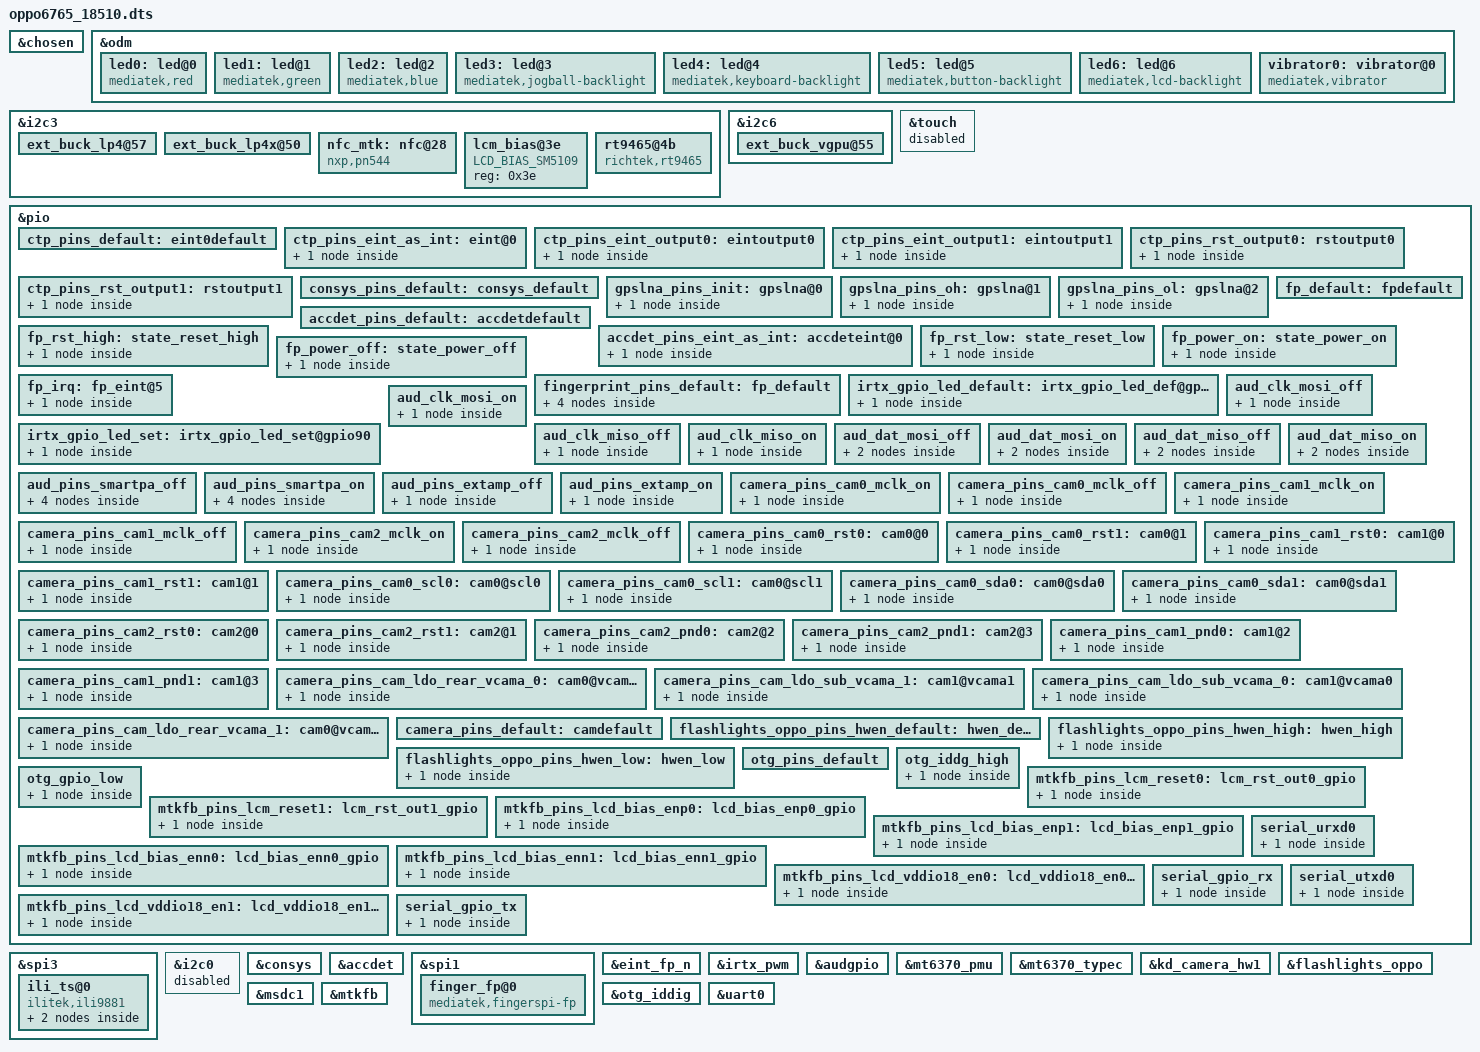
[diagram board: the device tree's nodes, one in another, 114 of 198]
#include <dt-bindings/interrupt-controller/arm-gic.h>
#include <dt-bindings/interrupt-controller/irq.h>
#include <dt-bindings/pinctrl/mt6765-pinfunc.h>
#include <dt-bindings/clock/mt6765-clk.h>
//#ifdef ODM_WT_EDIT
//Yanchao.Hu@ODM_WT.BSP.Storage.Sdcard, 2018/09/28, Modify for sdcard irq trigger states
#include <dt-bindings/mmc/mt6765-msdc.h>
//#endif

/dts-v1/;
/plugin/;

/* chosen */
&chosen {
	bootargs = "console=tty0 console=ttyS0,921600n1\
root=/dev/ram initrd=0x45000000,0x1000000 loglevel=8 \
androidboot.selinux=permissive androidboot.hardware=mt6765 \
initcall_debug=1 maxcpus=1";

	/* fpga may has no lk, we need to specify display info here */
	/* fb buffer is reserved using this dts by memory node above */
	atag,videolfb-fb_base_h = <0x0>;
	atag,videolfb-fb_base_l = <0x5e605000>;
	atag,videolfb-islcmfound = <1>;
	/* because no lk, so lcm is not inited */
	atag,videolfb-islcm_inited = <0>;
	atag,videolfb-fps= <6000>;
	atag,videolfb-vramSize= <0x017bb000>;
	atag,videolfb-lcmname= "nt35695B_fhd_dsi_cmd_auo_rt5081_drv";
};

&odm {
	led0:led@0 {
		compatible = "mediatek,red";
		led_mode = <0>;
		data = <1>;
		pwm_config = <0 0 0 0 0>;
	};
	led1:led@1 {
		compatible = "mediatek,green";
		led_mode = <0>;
		data = <1>;
		pwm_config = <0 0 0 0 0>;
	};
	led2:led@2 {
		compatible = "mediatek,blue";
		led_mode = <0>;
		data = <1>;
		pwm_config = <0 0 0 0 0>;
	};
	led3:led@3 {
		compatible = "mediatek,jogball-backlight";
		led_mode = <0>;
		data = <1>;
		pwm_config = <0 0 0 0 0>;
	};
	led4:led@4 {
		compatible = "mediatek,keyboard-backlight";
		led_mode = <0>;
		data = <1>;
		pwm_config = <0 0 0 0 0>;
	};
	led5:led@5 {
		compatible = "mediatek,button-backlight";
		led_mode = <0>;
		data = <1>;
		pwm_config = <0 0 0 0 0>;
	};
	led6:led@6 {
		compatible = "mediatek,lcd-backlight";
		led_mode = <4>;//ODM_WT_EDIT,backlight control by TDDIC
		data = <1>;
		pwm_config = <0 3 0 0 0>;
	};
	vibrator0:vibrator@0 {
		compatible = "mediatek,vibrator";
		vib_timer = <25>;
		vib_limit = <9>;
		vib_vol= <9>;
	};
};

&i2c3 {
	ext_buck_lp4@57 {
		regulator-name ="ext_buck_vdd2";
		regulator-min-microvolt = <300000>;
		regulator-max-microvolt = <1300000>;
		vsel_pin = <0>;
	};

	ext_buck_lp4x@50 {
		regulator-name ="ext_buck_vddq";
		regulator-min-microvolt = <300000>;
		regulator-max-microvolt = <1300000>;
		vsel_pin = <1>;
	};
/* #ifdef ODM_WT_EDIT */
	nfc_mtk:nfc@28 {
		compatible = "nxp,pn544";
		reg = <0x28>;
		pn544-irq = <&pio 97 0x0>;
		pn544-ven = <&pio 98 0x0>;
		pn544-fw-dwnld = <&pio 87 0x0>;
		pn544-clkreq = <&pio 89 0x0>;
		status = "okay";
	};
/* #endif */
};
/* #ifdef ODM_WT_EDIT */
/* Benzhong.Hou@ODM_WT.MM.Display.Lcd, 2018/10/10, add lcd gate ic device description */
/* lcd gate ic device description */
&i2c3 {
      lcm_bias@3e{
               compatible = "LCD_BIAS_SM5109","LCD_BIAS_NT50358A";
               reg = <0x3e>;
               status = "okay";
       };
};
/* Benzhong.Hou@ODM_WT.MM.Display.Lcd, 2018/10/10, add lcd gate ic device description */
/* #endif */
&i2c6 {
	ext_buck_vgpu@55 {
		regulator-name ="ext_buck_vgpu";
		regulator-min-microvolt = <300000>;
		regulator-max-microvolt = <1300000>;
		vsel_pin = <2>;
	};
};
/* TOUCH start */
&touch {
	tpd-resolution = <1080 1920>;
	use-tpd-button = <0>;
	tpd-key-num = <3>;
	tpd-key-local= <139 172 158 0>;
	tpd-key-dim-local = <90 883 100 40 230
				 883 100 40 370 883 100 40 0 0 0 0>;
	tpd-max-touch-num = <5>;
	tpd-filter-enable = <1>;
	tpd-filter-pixel-density = <146>;
	tpd-filter-custom-prameters = <0 0 0 0 0 0 0 0 0 0 0 0>;
	tpd-filter-custom-speed = <0 0 0>;
	pinctrl-names = "default", "state_eint_as_int", "state_eint_output0",
		"state_eint_output1", "state_rst_output0", "state_rst_output1";
	pinctrl-0 = <&ctp_pins_default>;
	pinctrl-1 = <&ctp_pins_eint_as_int>;
	pinctrl-2 = <&ctp_pins_eint_output0>;
	pinctrl-3 = <&ctp_pins_eint_output1>;
	pinctrl-4 = <&ctp_pins_rst_output0>;
	pinctrl-5 = <&ctp_pins_rst_output1>;
//#ifdef ODM_WT_EDIT
//Bin.Su@ODM_WT.BSP.TouchScreen, 2018/08/09, Disable no use dts for TouchScreen BringUp
	status = "disable";
//#endif
};
&pio {
	ctp_pins_default: eint0default {
	};
	ctp_pins_eint_as_int: eint@0 {
		pins_cmd_dat {
			pinmux = <PINMUX_GPIO0__FUNC_GPIO0>;
			slew-rate = <0>;
			bias-disable;
		};
	};
	ctp_pins_eint_output0: eintoutput0 {
		pins_cmd_dat {
			pinmux = <PINMUX_GPIO0__FUNC_GPIO0>;
			slew-rate = <1>;
			input-low;
		};
	};
	ctp_pins_eint_output1: eintoutput1 {
		pins_cmd_dat {
			pinmux = <PINMUX_GPIO0__FUNC_GPIO0>;
			slew-rate = <1>;
			input-high;
		};
	};
	ctp_pins_rst_output0: rstoutput0 {
		pins_cmd_dat {
			pinmux = <PINMUX_GPIO174__FUNC_GPIO174>;
			slew-rate = <1>;
			output-low;
		};
	};
	ctp_pins_rst_output1: rstoutput1 {
		pins_cmd_dat {
			pinmux = <PINMUX_GPIO174__FUNC_GPIO174>;
			slew-rate = <1>;
			output-high;
		};
	};
};
/* TOUCH end */

//#ifdef ODM_WT_EDIT
//Bin.Su@ODM_WT.BSP.TouchScreen, 2018/08/09, Add dts for TouchScreen BringUp
/*SPI touch start*/
&spi3 {
	#address-cells = <1>;
	#size-cells = <0>;
	ili_ts@0 {
		reg = <0>;
		compatible = "ilitek,ili9881","mediatek,cap_touch","novatek,NVT-ts-spi","himax,hx83112";
		touch,irq-gpio = <&pio 0 0>;
		touch,reset-gpio = <&pio 174 0>;

		focaltech,max-touch-number = <10>;
		focaltech,display-coords = <0 0 720 1520>;

		novatek,irq-gpio = <&pio 0 0>;
		novatek,reset-gpio = <&pio 174 0>;
		novatek,reset_global_gpio = <&pio 45 0>;
		/* 672A, 525B */
		novatek,swrst-n8-addr = <0x03F0FE>;
		/* MP */
		//novatek,mp-support-dt;

		spi-max-frequency = <9600000>;
		/*netlink-event = <30>;*/
		/* touchpanel configuration */
		touchpanel,rst-gpio = <&pio 174 0x0>;
		touchpanel,irq-gpio = <&pio 0 0x0>;
		touchpanel,open_short_not_use_fw;

		/*GPIO for LCD ID PIN*/
		touchpanel,id0-gpio = <&pio 169 0x0>;
		touchpanel,id1-gpio = <&pio 168 0x0>;
		touchpanel,id2-gpio = <&pio 172 0x0>;

		pinctrl-names = "default", "state_eint_as_int", "state_eint_output0",
		"state_eint_output1", "state_rst_output0", "state_rst_output1";
		pinctrl-0 = <&ctp_pins_default>;
		pinctrl-1 = <&ctp_pins_eint_as_int>;
		pinctrl-2 = <&ctp_pins_eint_output0>;
		pinctrl-3 = <&ctp_pins_eint_output1>;
		pinctrl-4 = <&ctp_pins_rst_output0>;
		pinctrl-5 = <&ctp_pins_rst_output1>;
		status = "ok";
		novatek,mp-support-dt;
		novatek-mp-criteria-tcl@0 {
			#address-cells = <1>;
			#size-cells = <0>;
			compatible = "novatek-mp-criteria-tcl";

			/* MP Config */
			IC_X_CFG_SIZE = <18>;
			IC_Y_CFG_SIZE = <32>;
			IC_KEY_CFG_SIZE = <4>;
			X_Channel = <18>;
			Y_Channel = <32>;
			AIN_X = <0 1 2 3 4 5 6 7 8 9 10 11 12 13 14 15 16 17>;
			AIN_Y = <0 1 2 3 4 5 6 7 8 9 10 11 12 13 14 15 16 17 18 19
								20 21 22 23 24 25 26 27 28 29 30 31>;
			AIN_KEY = <0 1 2 0xFF>;

			/* MP Criteria */
			PS_Config_Lmt_Short_Rawdata_P = <
				14008 14008 14008 14008 14008 14008 14008 14008 14008 14008 14008 14008 14008 14008 14008 14008 14008 14008
				14008 14008 14008 14008 14008 14008 14008 14008 14008 14008 14008 14008 14008 14008 14008 14008 14008 14008
				14008 14008 14008 14008 14008 14008 14008 14008 14008 14008 14008 14008 14008 14008 14008 14008 14008 14008
				14008 14008 14008 14008 14008 14008 14008 14008 14008 14008 14008 14008 14008 14008 14008 14008 14008 14008
				14008 14008 14008 14008 14008 14008 14008 14008 14008 14008 14008 14008 14008 14008 14008 14008 14008 14008
				14008 14008 14008 14008 14008 14008 14008 14008 14008 14008 14008 14008 14008 14008 14008 14008 14008 14008
				14008 14008 14008 14008 14008 14008 14008 14008 14008 14008 14008 14008 14008 14008 14008 14008 14008 14008
				14008 14008 14008 14008 14008 14008 14008 14008 14008 14008 14008 14008 14008 14008 14008 14008 14008 14008
				14008 14008 14008 14008 14008 14008 14008 14008 14008 14008 14008 14008 14008 14008 14008 14008 14008 14008
				14008 14008 14008 14008 14008 14008 14008 14008 14008 14008 14008 14008 14008 14008 14008 14008 14008 14008
				14008 14008 14008 14008 14008 14008 14008 14008 14008 14008 14008 14008 14008 14008 14008 14008 14008 14008
				14008 14008 14008 14008 14008 14008 14008 14008 14008 14008 14008 14008 14008 14008 14008 14008 14008 14008
				14008 14008 14008 14008 14008 14008 14008 14008 14008 14008 14008 14008 14008 14008 14008 14008 14008 14008
				14008 14008 14008 14008 14008 14008 14008 14008 14008 14008 14008 14008 14008 14008 14008 14008 14008 14008
				14008 14008 14008 14008 14008 14008 14008 14008 14008 14008 14008 14008 14008 14008 14008 14008 14008 14008
				14008 14008 14008 14008 14008 14008 14008 14008 14008 14008 14008 14008 14008 14008 14008 14008 14008 14008
				14008 14008 14008 14008 14008 14008 14008 14008 14008 14008 14008 14008 14008 14008 14008 14008 14008 14008
				14008 14008 14008 14008 14008 14008 14008 14008 14008 14008 14008 14008 14008 14008 14008 14008 14008 14008
				14008 14008 14008 14008 14008 14008 14008 14008 14008 14008 14008 14008 14008 14008 14008 14008 14008 14008
				14008 14008 14008 14008 14008 14008 14008 14008 14008 14008 14008 14008 14008 14008 14008 14008 14008 14008
				14008 14008 14008 14008 14008 14008 14008 14008 14008 14008 14008 14008 14008 14008 14008 14008 14008 14008
				14008 14008 14008 14008 14008 14008 14008 14008 14008 14008 14008 14008 14008 14008 14008 14008 14008 14008
				14008 14008 14008 14008 14008 14008 14008 14008 14008 14008 14008 14008 14008 14008 14008 14008 14008 14008
				14008 14008 14008 14008 14008 14008 14008 14008 14008 14008 14008 14008 14008 14008 14008 14008 14008 14008
				14008 14008 14008 14008 14008 14008 14008 14008 14008 14008 14008 14008 14008 14008 14008 14008 14008 14008
				14008 14008 14008 14008 14008 14008 14008 14008 14008 14008 14008 14008 14008 14008 14008 14008 14008 14008
				14008 14008 14008 14008 14008 14008 14008 14008 14008 14008 14008 14008 14008 14008 14008 14008 14008 14008
				14008 14008 14008 14008 14008 14008 14008 14008 14008 14008 14008 14008 14008 14008 14008 14008 14008 14008
				14008 14008 14008 14008 14008 14008 14008 14008 14008 14008 14008 14008 14008 14008 14008 14008 14008 14008
				14008 14008 14008 14008 14008 14008 14008 14008 14008 14008 14008 14008 14008 14008 14008 14008 14008 14008
				14008 14008 14008 14008 14008 14008 14008 14008 14008 14008 14008 14008 14008 14008 14008 14008 14008 14008
				14008 14008 14008 14008 14008 14008 14008 14008 14008 14008 14008 14008 14008 14008 14008 14008 14008 14008
				>;

			PS_Config_Lmt_Short_Rawdata_N = <
				11376 11376 11376 11376 11376 11376 11376 11376 11376 11376 11376 11376 11376 11376 11376 11376 11376 11376
				11376 11376 11376 11376 11376 11376 11376 11376 11376 11376 11376 11376 11376 11376 11376 11376 11376 11376
				11376 11376 11376 11376 11376 11376 11376 11376 11376 11376 11376 11376 11376 11376 11376 11376 11376 11376
				11376 11376 11376 11376 11376 11376 11376 11376 11376 11376 11376 11376 11376 11376 11376 11376 11376 11376
				11376 11376 11376 11376 11376 11376 11376 11376 11376 11376 11376 11376 11376 11376 11376 11376 11376 11376
				11376 11376 11376 11376 11376 11376 11376 11376 11376 11376 11376 11376 11376 11376 11376 11376 11376 11376
				11376 11376 11376 11376 11376 11376 11376 11376 11376 11376 11376 11376 11376 11376 11376 11376 11376 11376
				11376 11376 11376 11376 11376 11376 11376 11376 11376 11376 11376 11376 11376 11376 11376 11376 11376 11376
				11376 11376 11376 11376 11376 11376 11376 11376 11376 11376 11376 11376 11376 11376 11376 11376 11376 11376
				11376 11376 11376 11376 11376 11376 11376 11376 11376 11376 11376 11376 11376 11376 11376 11376 11376 11376
				11376 11376 11376 11376 11376 11376 11376 11376 11376 11376 11376 11376 11376 11376 11376 11376 11376 11376
				11376 11376 11376 11376 11376 11376 11376 11376 11376 11376 11376 11376 11376 11376 11376 11376 11376 11376
				11376 11376 11376 11376 11376 11376 11376 11376 11376 11376 11376 11376 11376 11376 11376 11376 11376 11376
				11376 11376 11376 11376 11376 11376 11376 11376 11376 11376 11376 11376 11376 11376 11376 11376 11376 11376
				11376 11376 11376 11376 11376 11376 11376 11376 11376 11376 11376 11376 11376 11376 11376 11376 11376 11376
				11376 11376 11376 11376 11376 11376 11376 11376 11376 11376 11376 11376 11376 11376 11376 11376 11376 11376
				11376 11376 11376 11376 11376 11376 11376 11376 11376 11376 11376 11376 11376 11376 11376 11376 11376 11376
				11376 11376 11376 11376 11376 11376 11376 11376 11376 11376 11376 11376 11376 11376 11376 11376 11376 11376
				11376 11376 11376 11376 11376 11376 11376 11376 11376 11376 11376 11376 11376 11376 11376 11376 11376 11376
				11376 11376 11376 11376 11376 11376 11376 11376 11376 11376 11376 11376 11376 11376 11376 11376 11376 11376
				11376 11376 11376 11376 11376 11376 11376 11376 11376 11376 11376 11376 11376 11376 11376 11376 11376 11376
				11376 11376 11376 11376 11376 11376 11376 11376 11376 11376 11376 11376 11376 11376 11376 11376 11376 11376
				11376 11376 11376 11376 11376 11376 11376 11376 11376 11376 11376 11376 11376 11376 11376 11376 11376 11376
				11376 11376 11376 11376 11376 11376 11376 11376 11376 11376 11376 11376 11376 11376 11376 11376 11376 11376
				11376 11376 11376 11376 11376 11376 11376 11376 11376 11376 11376 11376 11376 11376 11376 11376 11376 11376
				11376 11376 11376 11376 11376 11376 11376 11376 11376 11376 11376 11376 11376 11376 11376 11376 11376 11376
				11376 11376 11376 11376 11376 11376 11376 11376 11376 11376 11376 11376 11376 11376 11376 11376 11376 11376
				11376 11376 11376 11376 11376 11376 11376 11376 11376 11376 11376 11376 11376 11376 11376 11376 11376 11376
				11376 11376 11376 11376 11376 11376 11376 11376 11376 11376 11376 11376 11376 11376 11376 11376 11376 11376
				11376 11376 11376 11376 11376 11376 11376 11376 11376 11376 11376 11376 11376 11376 11376 11376 11376 11376
				11376 11376 11376 11376 11376 11376 11376 11376 11376 11376 11376 11376 11376 11376 11376 11376 11376 11376
				11376 11376 11376 11376 11376 11376 11376 11376 11376 11376 11376 11376 11376 11376 11376 11376 11376 11376
				>;

			PS_Config_Lmt_Open_Rawdata_P = <
				65535 4000 4000 4000 4000 4000 4000 4000 65535 65535 4000 4000 4000 4000 4000 4000 4000 65535
				4000 4000 4000 4000 4000 4000 4000 4000 4000 4000 4000 4000 4000 4000 4000 4000 4000 4000
				4000 4000 4000 4000 4000 4000 4000 4000 4000 4000 4000 4000 4000 4000 4000 4000 4000 4000
				4000 4000 4000 4000 4000 4000 4000 4000 4000 4000 4000 4000 4000 4000 4000 4000 4000 4000
				4000 4000 4000 4000 4000 4000 4000 4000 4000 4000 4000 4000 4000 4000 4000 4000 4000 4000
				4000 4000 4000 4000 4000 4000 4000 4000 4000 4000 4000 4000 4000 4000 4000 4000 4000 4000
				4000 4000 4000 4000 4000 4000 4000 4000 4000 4000 4000 4000 4000 4000 4000 4000 4000 4000
				4000 4000 4000 4000 4000 4000 4000 4000 4000 4000 4000 4000 4000 4000 4000 4000 4000 4000
				4000 4000 4000 4000 4000 4000 4000 4000 4000 4000 4000 4000 4000 4000 4000 4000 4000 4000
				4000 4000 4000 4000 4000 4000 4000 4000 4000 4000 4000 4000 4000 4000 4000 4000 4000 4000
				4000 4000 4000 4000 4000 4000 4000 4000 4000 4000 4000 4000 4000 4000 4000 4000 4000 4000
				4000 4000 4000 4000 4000 4000 4000 4000 4000 4000 4000 4000 4000 4000 4000 4000 4000 4000
				4000 4000 4000 4000 4000 4000 4000 4000 4000 4000 4000 4000 4000 4000 4000 4000 4000 4000
				4000 4000 4000 4000 4000 4000 4000 4000 4000 4000 4000 4000 4000 4000 4000 4000 4000 4000
				4000 4000 4000 4000 4000 4000 4000 4000 4000 4000 4000 4000 4000 4000 4000 4000 4000 4000
				4000 4000 4000 4000 4000 4000 4000 4000 4000 4000 4000 4000 4000 4000 4000 4000 4000 4000
				4000 4000 4000 4000 4000 4000 4000 4000 4000 4000 4000 4000 4000 4000 4000 4000 4000 4000
				4000 4000 4000 4000 4000 4000 4000 4000 4000 4000 4000 4000 4000 4000 4000 4000 4000 4000
				4000 4000 4000 4000 4000 4000 4000 4000 4000 4000 4000 4000 4000 4000 4000 4000 4000 4000
				4000 4000 4000 4000 4000 4000 4000 4000 4000 4000 4000 4000 4000 4000 4000 4000 4000 4000
				4000 4000 4000 4000 4000 4000 4000 4000 4000 4000 4000 4000 4000 4000 4000 4000 4000 4000
				4000 4000 4000 4000 4000 4000 4000 4000 4000 4000 4000 4000 4000 4000 4000 4000 4000 4000
				4000 4000 4000 4000 4000 4000 4000 4000 4000 4000 4000 4000 4000 4000 4000 4000 4000 4000
				4000 4000 4000 4000 4000 4000 4000 4000 4000 4000 4000 4000 4000 4000 4000 4000 4000 4000
				4000 4000 4000 4000 4000 4000 4000 4000 4000 4000 4000 4000 4000 4000 4000 4000 4000 4000
				4000 4000 4000 4000 4000 4000 4000 4000 4000 4000 4000 4000 4000 4000 4000 4000 4000 4000
				4000 4000 4000 4000 4000 4000 4000 4000 4000 4000 4000 4000 4000 4000 4000 4000 4000 4000
				4000 4000 4000 4000 4000 4000 4000 4000 4000 4000 4000 4000 4000 4000 4000 4000 4000 4000
				4000 4000 4000 4000 4000 4000 4000 4000 4000 4000 4000 4000 4000 4000 4000 4000 4000 4000
				4000 4000 4000 4000 4000 4000 4000 4000 4000 4000 4000 4000 4000 4000 4000 4000 4000 4000
				4000 4000 4000 4000 4000 4000 4000 4000 4000 4000 4000 4000 4000 4000 4000 4000 4000 4000
				4000 4000 4000 4000 4000 4000 4000 4000 4000 4000 4000 4000 4000 4000 4000 4000 4000 4000
				>;

			PS_Config_Lmt_Open_Rawdata_N = <
				0 400 400 400 400 400 400 400 0 0 400 400 400 400 400 400 400 0
				400 400 400 400 400 400 400 400 400 400 400 400 400 400 400 400 400 400
				400 400 400 400 400 400 400 400 400 400 400 400 400 400 400 400 400 400
				400 400 400 400 400 400 400 400 400 400 400 400 400 400 400 400 400 400
				400 400 400 400 400 400 400 400 400 400 400 400 400 400 400 400 400 400
				400 400 400 400 400 400 400 400 400 400 400 400 400 400 400 400 400 400
				400 400 400 400 400 400 400 400 400 400 400 400 400 400 400 400 400 400
				400 400 400 400 400 400 400 400 400 400 400 400 400 400 400 400 400 400
				400 400 400 400 400 400 400 400 400 400 400 400 400 400 400 400 400 400
				400 400 400 400 400 400 400 400 400 400 400 400 400 400 400 400 400 400
				400 400 400 400 400 400 400 400 400 400 400 400 400 400 400 400 400 400
				400 400 400 400 400 400 400 400 400 400 400 400 400 400 400 400 400 400
				400 400 400 400 400 400 400 400 400 400 400 400 400 400 400 400 400 400
				400 400 400 400 400 400 400 400 400 400 400 400 400 400 400 400 400 400
				400 400 400 400 400 400 400 400 400 400 400 400 400 400 400 400 400 400
				400 400 400 400 400 400 400 400 400 400 400 400 400 400 400 400 400 400
				400 400 400 400 400 400 400 400 400 400 400 400 400 400 400 400 400 400
				400 400 400 400 400 400 400 400 400 400 400 400 400 400 400 400 400 400
				400 400 400 400 400 400 400 400 400 400 400 400 400 400 400 400 400 400
				400 400 400 400 400 400 400 400 400 400 400 400 400 400 400 400 400 400
				400 400 400 400 400 400 400 400 400 400 400 400 400 400 400 400 400 400
				400 400 400 400 400 400 400 400 400 400 400 400 400 400 400 400 400 400
				400 400 400 400 400 400 400 400 400 400 400 400 400 400 400 400 400 400
				400 400 400 400 400 400 400 400 400 400 400 400 400 400 400 400 400 400
				400 400 400 400 400 400 400 400 400 400 400 400 400 400 400 400 400 400
				400 400 400 400 400 400 400 400 400 400 400 400 400 400 400 400 400 400
				400 400 400 400 400 400 400 400 400 400 400 400 400 400 400 400 400 400
				400 400 400 400 400 400 400 400 400 400 400 400 400 400 400 400 400 400
				400 400 400 400 400 400 400 400 400 400 400 400 400 400 400 400 400 400
				400 400 400 400 400 400 400 400 400 400 400 400 400 400 400 400 400 400
				400 400 400 400 400 400 400 400 400 400 400 400 400 400 400 400 400 400
				400 400 400 400 400 400 400 400 400 400 400 400 400 400 400 400 400 400
				>;

			PS_Config_Lmt_FW_Rawdata_P = <
				65535 1600 1600 1600 1600 1600 1600 1600 65535 65535 1600 1600 1600 1600 1600 1600 1600 65535
				1600 1600 1600 1600 1600 1600 1600 1600 1600 1600 1600 1600 1600 1600 1600 1600 1600 1600
				1600 1600 1600 1600 1600 1600 1600 1600 1600 1600 1600 1600 1600 1600 1600 1600 1600 1600
				1600 1600 1600 1600 1600 1600 1600 1600 1600 1600 1600 1600 1600 1600 1600 1600 1600 1600
				1600 1600 1600 1600 1600 1600 1600 1600 1600 1600 1600 1600 1600 1600 1600 1600 1600 1600
				1600 1600 1600 1600 1600 1600 1600 1600 1600 1600 1600 1600 1600 1600 1600 1600 1600 1600
				1600 1600 1600 1600 1600 1600 1600 1600 1600 1600 1600 1600 1600 1600 1600 1600 1600 1600
				1600 1600 1600 1600 1600 1600 1600 1600 1600 1600 1600 1600 1600 1600 1600 1600 1600 1600
				1600 1600 1600 1600 1600 1600 1600 1600 1600 1600 1600 1600 1600 1600 1600 1600 1600 1600
				1600 1600 1600 1600 1600 1600 1600 1600 1600 1600 1600 1600 1600 1600 1600 1600 1600 1600
				1600 1600 1600 1600 1600 1600 1600 1600 1600 1600 1600 1600 1600 1600 1600 1600 1600 1600
				1600 1600 1600 1600 1600 1600 1600 1600 1600 1600 1600 1600 1600 1600 1600 1600 1600 1600
				1600 1600 1600 1600 1600 1600 1600 1600 1600 1600 1600 1600 1600 1600 1600 1600 1600 1600
				1600 1600 1600 1600 1600 1600 1600 1600 1600 1600 1600 1600 1600 1600 1600 1600 1600 1600
				1600 1600 1600 1600 1600 1600 1600 1600 1600 1600 1600 1600 1600 1600 1600 1600 1600 1600
				1600 1600 1600 1600 1600 1600 1600 1600 1600 1600 1600 1600 1600 1600 1600 1600 1600 1600
				1600 1600 1600 1600 1600 1600 1600 1600 1600 1600 1600 1600 1600 1600 1600 1600 1600 1600
				1600 1600 1600 1600 1600 1600 1600 1600 1600 1600 1600 1600 1600 1600 1600 1600 1600 1600
				1600 1600 1600 1600 1600 1600 1600 1600 1600 1600 1600 1600 1600 1600 1600 1600 1600 1600
				1600 1600 1600 1600 1600 1600 1600 1600 1600 1600 1600 1600 1600 1600 1600 1600 1600 1600
				1600 1600 1600 1600 1600 1600 1600 1600 1600 1600 1600 1600 1600 1600 1600 1600 1600 1600
				1600 1600 1600 1600 1600 1600 1600 1600 1600 1600 1600 1600 1600 1600 1600 1600 1600 1600
				1600 1600 1600 1600 1600 1600 1600 1600 1600 1600 1600 1600 1600 1600 1600 1600 1600 1600
				1600 1600 1600 1600 1600 1600 1600 1600 1600 1600 1600 1600 1600 1600 1600 1600 1600 1600
				1600 1600 1600 1600 1600 1600 1600 1600 1600 1600 1600 1600 1600 1600 1600 1600 1600 1600
				1600 1600 1600 1600 1600 1600 1600 1600 1600 1600 1600 1600 1600 1600 1600 1600 1600 1600
				1600 1600 1600 1600 1600 1600 1600 1600 1600 1600 1600 1600 1600 1600 1600 1600 1600 1600
				1600 1600 1600 1600 1600 1600 1600 1600 1600 1600 1600 1600 1600 1600 1600 1600 1600 1600
				1600 1600 1600 1600 1600 1600 1600 1600 1600 1600 1600 1600 1600 1600 1600 1600 1600 1600
				1600 1600 1600 1600 1600 1600 1600 1600 1600 1600 1600 1600 1600 1600 1600 1600 1600 1600
				1600 1600 1600 1600 1600 1600 1600 1600 1600 1600 1600 1600 1600 1600 1600 1600 1600 1600
				1600 1600 1600 1600 1600 1600 1600 1600 1600 1600 1600 1600 1600 1600 1600 1600 1600 1600
				>;

			PS_Config_Lmt_FW_Rawdata_N = <
				0 200 200 200 200 200 200 200 0 0 200 200 200 200 200 200 200 0
				200 200 200 200 200 200 200 200 200 200 200 200 200 200 200 200 200 200
				200 200 200 200 200 200 200 200 200 200 200 200 200 200 200 200 200 200
				200 200 200 200 200 200 200 200 200 200 200 200 200 200 200 200 200 200
				200 200 200 200 200 200 200 200 200 200 200 200 200 200 200 200 200 200
				200 200 200 200 200 200 200 200 200 200 200 200 200 200 200 200 200 200
				200 200 200 200 200 200 200 200 200 200 200 200 200 200 200 200 200 200
				200 200 200 200 200 200 200 200 200 200 200 200 200 200 200 200 200 200
				200 200 200 200 200 200 200 200 200 200 200 200 200 200 200 200 200 200
				200 200 200 200 200 200 200 200 200 200 200 200 200 200 200 200 200 200
				200 200 200 200 200 200 200 200 200 200 200 200 200 200 200 200 200 200
				200 200 200 200 200 200 200 200 200 200 200 200 200 200 200 200 200 200
				200 200 200 200 200 200 200 200 200 200 200 200 200 200 200 200 200 200
				200 200 200 200 200 200 200 200 200 200 200 200 200 200 200 200 200 200
				200 200 200 200 200 200 200 200 200 200 200 200 200 200 200 200 200 200
				200 200 200 200 200 200 200 200 200 200 200 200 200 200 200 200 200 200
				200 200 200 200 200 200 200 200 200 200 200 200 200 200 200 200 200 200
				200 200 200 200 200 200 200 200 200 200 200 200 200 200 200 200 200 200
				200 200 200 200 200 200 200 200 200 200 200 200 200 200 200 200 200 200
				200 200 200 200 200 200 200 200 200 200 200 200 200 200 200 200 200 200
				200 200 200 200 200 200 200 200 200 200 200 200 200 200 200 200 200 200
				200 200 200 200 200 200 200 200 200 200 200 200 200 200 200 200 200 200
				200 200 200 200 200 200 200 200 200 200 200 200 200 200 200 200 200 200
				200 200 200 200 200 200 200 200 200 200 200 200 200 200 200 200 200 200
				200 200 200 200 200 200 200 200 200 200 200 200 200 200 200 200 200 200
				200 200 200 200 200 200 200 200 200 200 200 200 200 200 200 200 200 200
				200 200 200 200 200 200 200 200 200 200 200 200 200 200 200 200 200 200
				200 200 200 200 200 200 200 200 200 200 200 200 200 200 200 200 200 200
				200 200 200 200 200 200 200 200 200 200 200 200 200 200 200 200 200 200
				200 200 200 200 200 200 200 200 200 200 200 200 200 200 200 200 200 200
				200 200 200 200 200 200 200 200 200 200 200 200 200 200 200 200 200 200
				200 200 200 200 200 200 200 200 200 200 200 200 200 200 200 200 200 200
				>;

			PS_Config_Lmt_FW_CC_P = <
				200 200 200 200 200 200 200 200 200 200 200 200 200 200 200 200 200 200
				200 200 200 200 200 200 200 200 200 200 200 200 200 200 200 200 200 200
				200 200 200 200 200 200 200 200 200 200 200 200 200 200 200 200 200 200
				200 200 200 200 200 200 200 200 200 200 200 200 200 200 200 200 200 200
				200 200 200 200 200 200 200 200 200 200 200 200 200 200 200 200 200 200
				200 200 200 200 200 200 200 200 200 200 200 200 200 200 200 200 200 200
				200 200 200 200 200 200 200 200 200 200 200 200 200 200 200 200 200 200
				200 200 200 200 200 200 200 200 200 200 200 200 200 200 200 200 200 200
				200 200 200 200 200 200 200 200 200 200 200 200 200 200 200 200 200 200
				200 200 200 200 200 200 200 200 200 200 200 200 200 200 200 200 200 200
				200 200 200 200 200 200 200 200 200 200 200 200 200 200 200 200 200 200
				200 200 200 200 200 200 200 200 200 200 200 200 200 200 200 200 200 200
				200 200 200 200 200 200 200 200 200 200 200 200 200 200 200 200 200 200
				200 200 200 200 200 200 200 200 200 200 200 200 200 200 200 200 200 200
				200 200 200 200 200 200 200 200 200 200 200 200 200 200 200 200 200 200
				200 200 200 200 200 200 200 200 200 200 200 200 200 200 200 200 200 200
				200 200 200 200 200 200 200 200 200 200 200 200 200 200 200 200 200 200
				200 200 200 200 200 200 200 200 200 200 200 200 200 200 200 200 200 200
				200 200 200 200 200 200 200 200 200 200 200 200 200 200 200 200 200 200
				200 200 200 200 200 200 200 200 200 200 200 200 200 200 200 200 200 200
				200 200 200 200 200 200 200 200 200 200 200 200 200 200 200 200 200 200
				200 200 200 200 200 200 200 200 200 200 200 200 200 200 200 200 200 200
				200 200 200 200 200 200 200 200 200 200 200 200 200 200 200 200 200 200
				200 200 200 200 200 200 200 200 200 200 200 200 200 200 200 200 200 200
				200 200 200 200 200 200 200 200 200 200 200 200 200 200 200 200 200 200
				200 200 200 200 200 200 200 200 200 200 200 200 200 200 200 200 200 200
				200 200 200 200 200 200 200 200 200 200 200 200 200 200 200 200 200 200
				200 200 200 200 200 200 200 200 200 200 200 200 200 200 200 200 200 200
				200 200 200 200 200 200 200 200 200 200 200 200 200 200 200 200 200 200
				200 200 200 200 200 200 200 200 200 200 200 200 200 200 200 200 200 200
				200 200 200 200 200 200 200 200 200 200 200 200 200 200 200 200 200 200
				200 200 200 200 200 200 200 200 200 200 200 200 200 200 200 200 200 200
				>;

			PS_Config_Lmt_FW_CC_N = <
				0 30 30 30 30 30 30 30 0 0 30 30 30 30 30 30 30 0
				30 30 30 30 30 30 30 30 30 30 30 30 30 30 30 30 30 30
				30 30 30 30 30 30 30 30 30 30 30 30 30 30 30 30 30 30
				30 30 30 30 30 30 30 30 30 30 30 30 30 30 30 30 30 30
				30 30 30 30 30 30 30 30 30 30 30 30 30 30 30 30 30 30
				30 30 30 30 30 30 30 30 30 30 30 30 30 30 30 30 30 30
				30 30 30 30 30 30 30 30 30 30 30 30 30 30 30 30 30 30
				30 30 30 30 30 30 30 30 30 30 30 30 30 30 30 30 30 30
				30 30 30 30 30 30 30 30 30 30 30 30 30 30 30 30 30 30
				30 30 30 30 30 30 30 30 30 30 30 30 30 30 30 30 30 30
				30 30 30 30 30 30 30 30 30 30 30 30 30 30 30 30 30 30
				30 30 30 30 30 30 30 30 30 30 30 30 30 30 30 30 30 30
				30 30 30 30 30 30 30 30 30 30 30 30 30 30 30 30 30 30
				30 30 30 30 30 30 30 30 30 30 30 30 30 30 30 30 30 30
				30 30 30 30 30 30 30 30 30 30 30 30 30 30 30 30 30 30
				30 30 30 30 30 30 30 30 30 30 30 30 30 30 30 30 30 30
				30 30 30 30 30 30 30 30 30 30 30 30 30 30 30 30 30 30
				30 30 30 30 30 30 30 30 30 30 30 30 30 30 30 30 30 30
				30 30 30 30 30 30 30 30 30 30 30 30 30 30 30 30 30 30
				30 30 30 30 30 30 30 30 30 30 30 30 30 30 30 30 30 30
				30 30 30 30 30 30 30 30 30 30 30 30 30 30 30 30 30 30
				30 30 30 30 30 30 30 30 30 30 30 30 30 30 30 30 30 30
				30 30 30 30 30 30 30 30 30 30 30 30 30 30 30 30 30 30
				30 30 30 30 30 30 30 30 30 30 30 30 30 30 30 30 30 30
				30 30 30 30 30 30 30 30 30 30 30 30 30 30 30 30 30 30
				30 30 30 30 30 30 30 30 30 30 30 30 30 30 30 30 30 30
				30 30 30 30 30 30 30 30 30 30 30 30 30 30 30 30 30 30
				30 30 30 30 30 30 30 30 30 30 30 30 30 30 30 30 30 30
				30 30 30 30 30 30 30 30 30 30 30 30 30 30 30 30 30 30
				30 30 30 30 30 30 30 30 30 30 30 30 30 30 30 30 30 30
				30 30 30 30 30 30 30 30 30 30 30 30 30 30 30 30 30 30
				30 30 30 30 30 30 30 30 30 30 30 30 30 30 30 30 30 30
				>;

			PS_Config_Lmt_FW_Diff_P = <
				65535 80 80 80 80 80 80 80 65535 65535 80 80 80 80 80 80 80 65535
				80 80 80 80 80 80 80 80 80 80 80 80 80 80 80 80 80 80
				80 80 80 80 80 80 80 80 80 80 80 80 80 80 80 80 80 80
				80 80 80 80 80 80 80 80 80 80 80 80 80 80 80 80 80 80
				80 80 80 80 80 80 80 80 80 80 80 80 80 80 80 80 80 80
				80 80 80 80 80 80 80 80 80 80 80 80 80 80 80 80 80 80
				80 80 80 80 80 80 80 80 80 80 80 80 80 80 80 80 80 80
				80 80 80 80 80 80 80 80 80 80 80 80 80 80 80 80 80 80
				80 80 80 80 80 80 80 80 80 80 80 80 80 80 80 80 80 80
				80 80 80 80 80 80 80 80 80 80 80 80 80 80 80 80 80 80
				80 80 80 80 80 80 80 80 80 80 80 80 80 80 80 80 80 80
				80 80 80 80 80 80 80 80 80 80 80 80 80 80 80 80 80 80
				80 80 80 80 80 80 80 80 80 80 80 80 80 80 80 80 80 80
				80 80 80 80 80 80 80 80 80 80 80 80 80 80 80 80 80 80
				80 80 80 80 80 80 80 80 80 80 80 80 80 80 80 80 80 80
				80 80 80 80 80 80 80 80 80 80 80 80 80 80 80 80 80 80
				80 80 80 80 80 80 80 80 80 80 80 80 80 80 80 80 80 80
				80 80 80 80 80 80 80 80 80 80 80 80 80 80 80 80 80 80
				80 80 80 80 80 80 80 80 80 80 80 80 80 80 80 80 80 80
				80 80 80 80 80 80 80 80 80 80 80 80 80 80 80 80 80 80
				80 80 80 80 80 80 80 80 80 80 80 80 80 80 80 80 80 80
				80 80 80 80 80 80 80 80 80 80 80 80 80 80 80 80 80 80
				80 80 80 80 80 80 80 80 80 80 80 80 80 80 80 80 80 80
				80 80 80 80 80 80 80 80 80 80 80 80 80 80 80 80 80 80
				80 80 80 80 80 80 80 80 80 80 80 80 80 80 80 80 80 80
				80 80 80 80 80 80 80 80 80 80 80 80 80 80 80 80 80 80
				80 80 80 80 80 80 80 80 80 80 80 80 80 80 80 80 80 80
				80 80 80 80 80 80 80 80 80 80 80 80 80 80 80 80 80 80
				80 80 80 80 80 80 80 80 80 80 80 80 80 80 80 80 80 80
				80 80 80 80 80 80 80 80 80 80 80 80 80 80 80 80 80 80
				80 80 80 80 80 80 80 80 80 80 80 80 80 80 80 80 80 80
				80 80 80 80 80 80 80 80 80 80 80 80 80 80 80 80 80 80
				>;

			PS_Config_Lmt_FW_Diff_N = <
				(-65535) (-80) (-80) (-80) (-80) (-80) (-80) (-80) (-65535) (-65535) (-80) (-80) (-80) (-80) (-80) (-80) (-80) (-65535)
				(-80) (-80) (-80) (-80) (-80) (-80)    (-80)    (-80)    (-80)    (-80)    (-80)    (-80) (-80) (-80) (-80) (-80) (-80) (-80)
				(-80) (-80) (-80) (-80) (-80) (-80)    (-80)    (-80)    (-80)    (-80)    (-80)    (-80) (-80) (-80) (-80) (-80) (-80) (-80)
				(-80) (-80) (-80) (-80) (-80) (-80)    (-80)    (-80)    (-80)    (-80)    (-80)    (-80) (-80) (-80) (-80) (-80) (-80) (-80)
				(-80) (-80) (-80) (-80) (-80) (-80)    (-80)    (-80)    (-80)    (-80)    (-80)    (-80) (-80) (-80) (-80) (-80) (-80) (-80)
				(-80) (-80) (-80) (-80) (-80) (-80)    (-80)    (-80)    (-80)    (-80)    (-80)    (-80) (-80) (-80) (-80) (-80) (-80) (-80)
				(-80) (-80) (-80) (-80) (-80) (-80)    (-80)    (-80)    (-80)    (-80)    (-80)    (-80) (-80) (-80) (-80) (-80) (-80) (-80)
				(-80) (-80) (-80) (-80) (-80) (-80)    (-80)    (-80)    (-80)    (-80)    (-80)    (-80) (-80) (-80) (-80) (-80) (-80) (-80)
				(-80) (-80) (-80) (-80) (-80) (-80)    (-80)    (-80)    (-80)    (-80)    (-80)    (-80) (-80) (-80) (-80) (-80) (-80) (-80)
				(-80) (-80) (-80) (-80) (-80) (-80)    (-80)    (-80)    (-80)    (-80)    (-80)    (-80) (-80) (-80) (-80) (-80) (-80) (-80)
				(-80) (-80) (-80) (-80) (-80) (-80)    (-80)    (-80)    (-80)    (-80)    (-80)    (-80) (-80) (-80) (-80) (-80) (-80) (-80)
				(-80) (-80) (-80) (-80) (-80) (-80)    (-80)    (-80)    (-80)    (-80)    (-80)    (-80) (-80) (-80) (-80) (-80) (-80) (-80)
				(-80) (-80) (-80) (-80) (-80) (-80)    (-80)    (-80)    (-80)    (-80)    (-80)    (-80) (-80) (-80) (-80) (-80) (-80) (-80)
				(-80) (-80) (-80) (-80) (-80) (-80)    (-80)    (-80)    (-80)    (-80)    (-80)    (-80) (-80) (-80) (-80) (-80) (-80) (-80)
				(-80) (-80) (-80) (-80) (-80) (-80)    (-80)    (-80)    (-80)    (-80)    (-80)    (-80) (-80) (-80) (-80) (-80) (-80) (-80)
				(-80) (-80) (-80) (-80) (-80) (-80)    (-80)    (-80)    (-80)    (-80)    (-80)    (-80) (-80) (-80) (-80) (-80) (-80) (-80)
				(-80) (-80) (-80) (-80) (-80) (-80)    (-80)    (-80)    (-80)    (-80)    (-80)    (-80) (-80) (-80) (-80) (-80) (-80) (-80)
				(-80) (-80) (-80) (-80) (-80) (-80)    (-80)    (-80)    (-80)    (-80)    (-80)    (-80) (-80) (-80) (-80) (-80) (-80) (-80)
				(-80) (-80) (-80) (-80) (-80) (-80)    (-80)    (-80)    (-80)    (-80)    (-80)    (-80) (-80) (-80) (-80) (-80) (-80) (-80)
				(-80) (-80) (-80) (-80) (-80) (-80)    (-80)    (-80)    (-80)    (-80)    (-80)    (-80) (-80) (-80) (-80) (-80) (-80) (-80)
				(-80) (-80) (-80) (-80) (-80) (-80)    (-80)    (-80)    (-80)    (-80)    (-80)    (-80) (-80) (-80) (-80) (-80) (-80) (-80)
				(-80) (-80) (-80) (-80) (-80) (-80)    (-80)    (-80)    (-80)    (-80)    (-80)    (-80) (-80) (-80) (-80) (-80) (-80) (-80)
				(-80) (-80) (-80) (-80) (-80) (-80)    (-80)    (-80)    (-80)    (-80)    (-80)    (-80) (-80) (-80) (-80) (-80) (-80) (-80)
				(-80) (-80) (-80) (-80) (-80) (-80)    (-80)    (-80)    (-80)    (-80)    (-80)    (-80) (-80) (-80) (-80) (-80) (-80) (-80)
				(-80) (-80) (-80) (-80) (-80) (-80)    (-80)    (-80)    (-80)    (-80)    (-80)    (-80) (-80) (-80) (-80) (-80) (-80) (-80)
				(-80) (-80) (-80) (-80) (-80) (-80)    (-80)    (-80)    (-80)    (-80)    (-80)    (-80) (-80) (-80) (-80) (-80) (-80) (-80)
				(-80) (-80) (-80) (-80) (-80) (-80)    (-80)    (-80)    (-80)    (-80)    (-80)    (-80) (-80) (-80) (-80) (-80) (-80) (-80)
				(-80) (-80) (-80) (-80) (-80) (-80)    (-80)    (-80)    (-80)    (-80)    (-80)    (-80) (-80) (-80) (-80) (-80) (-80) (-80)
				(-80) (-80) (-80) (-80) (-80) (-80)    (-80)    (-80)    (-80)    (-80)    (-80)    (-80) (-80) (-80) (-80) (-80) (-80) (-80)
				(-80) (-80) (-80) (-80) (-80) (-80)    (-80)    (-80)    (-80)    (-80)    (-80)    (-80) (-80) (-80) (-80) (-80) (-80) (-80)
				(-80) (-80) (-80) (-80) (-80) (-80)    (-80)    (-80)    (-80)    (-80)    (-80)    (-80) (-80) (-80) (-80) (-80) (-80) (-80)
				(-80) (-80) (-80) (-80) (-80) (-80)    (-80)    (-80)    (-80)    (-80)    (-80)    (-80) (-80) (-80) (-80) (-80) (-80) (-80)
				>;

			PS_Config_Diff_Test_Frame = <50>;

			PS_Config_Lmt_LPWG_Rawdata_P = <
				65535 1600 1600 1600 1600 1600  1600 1600 65535 65535 1600 1600 1600 1600 1600 1600 1600 65535
				1600 1600 1600 1600 1600 1600   1600   1600   1600   1600   1600   1600 1600 1600 1600 1600 1600 1600
				1600 1600 1600 1600 1600 1600   1600   1600   1600   1600   1600   1600 1600 1600 1600 1600 1600 1600
				1600 1600 1600 1600 1600 1600   1600   1600   1600   1600   1600   1600 1600 1600 1600 1600 1600 1600
				1600 1600 1600 1600 1600 1600   1600   1600   1600   1600   1600   1600 1600 1600 1600 1600 1600 1600
				1600 1600 1600 1600 1600 1600   1600   1600   1600   1600   1600   1600 1600 1600 1600 1600 1600 1600
				1600 1600 1600 1600 1600 1600   1600   1600   1600   1600   1600   1600 1600 1600 1600 1600 1600 1600
				1600 1600 1600 1600 1600 1600   1600   1600   1600   1600   1600   1600 1600 1600 1600 1600 1600 1600
				1600 1600 1600 1600 1600 1600   1600   1600   1600   1600   1600   1600 1600 1600 1600 1600 1600 1600
				1600 1600 1600 1600 1600 1600   1600   1600   1600   1600   1600   1600 1600 1600 1600 1600 1600 1600
				1600 1600 1600 1600 1600 1600   1600   1600   1600   1600   1600   1600 1600 1600 1600 1600 1600 1600
				1600 1600 1600 1600 1600 1600   1600   1600   1600   1600   1600   1600 1600 1600 1600 1600 1600 1600
				1600 1600 1600 1600 1600 1600   1600   1600   1600   1600   1600   1600 1600 1600 1600 1600 1600 1600
				1600 1600 1600 1600 1600 1600   1600   1600   1600   1600   1600   1600 1600 1600 1600 1600 1600 1600
				1600 1600 1600 1600 1600 1600   1600   1600   1600   1600   1600   1600 1600 1600 1600 1600 1600 1600
				1600 1600 1600 1600 1600 1600   1600   1600   1600   1600   1600   1600 1600 1600 1600 1600 1600 1600
				1600 1600 1600 1600 1600 1600   1600   1600   1600   1600   1600   1600 1600 1600 1600 1600 1600 1600
				1600 1600 1600 1600 1600 1600   1600   1600   1600   1600   1600   1600 1600 1600 1600 1600 1600 1600
				1600 1600 1600 1600 1600 1600   1600   1600   1600   1600   1600   1600 1600 1600 1600 1600 1600 1600
				1600 1600 1600 1600 1600 1600   1600   1600   1600   1600   1600   1600 1600 1600 1600 1600 1600 1600
				1600 1600 1600 1600 1600 1600   1600   1600   1600   1600   1600   1600 1600 1600 1600 1600 1600 1600
				1600 1600 1600 1600 1600 1600   1600   1600   1600   1600   1600   1600 1600 1600 1600 1600 1600 1600
				1600 1600 1600 1600 1600 1600   1600   1600   1600   1600   1600   1600 1600 1600 1600 1600 1600 1600
				1600 1600 1600 1600 1600 1600   1600   1600   1600   1600   1600   1600 1600 1600 1600 1600 1600 1600
				1600 1600 1600 1600 1600 1600   1600   1600   1600   1600   1600   1600 1600 1600 1600 1600 1600 1600
				1600 1600 1600 1600 1600 1600   1600   1600   1600   1600   1600   1600 1600 1600 1600 1600 1600 1600
				1600 1600 1600 1600 1600 1600   1600   1600   1600   1600   1600   1600 1600 1600 1600 1600 1600 1600
				1600 1600 1600 1600 1600 1600   1600   1600   1600   1600   1600   1600 1600 1600 1600 1600 1600 1600
				1600 1600 1600 1600 1600 1600   1600   1600   1600   1600   1600   1600 1600 1600 1600 1600 1600 1600
				1600 1600 1600 1600 1600 1600   1600   1600   1600   1600   1600   1600 1600 1600 1600 1600 1600 1600
				1600 1600 1600 1600 1600 1600   1600   1600   1600   1600   1600   1600 1600 1600 1600 1600 1600 1600
				1600 1600 1600 1600 1600 1600   1600   1600   1600   1600   1600   1600 1600 1600 1600 1600 1600 1600
				>;

			PS_Config_Lmt_LPWG_Rawdata_N = <
				0 200 200 200 200 200   200   200   0   0   200   200 200 200 200 200 200 0
				200 200 200 200 200 200 200 200 200 200 200 200 200 200 200 200 200 200
				200 200 200 200 200 200 200 200 200 200 200 200 200 200 200 200 200 200
				200 200 200 200 200 200 200 200 200 200 200 200 200 200 200 200 200 200
				200 200 200 200 200 200 200 200 200 200 200 200 200 200 200 200 200 200
				200 200 200 200 200 200 200 200 200 200 200 200 200 200 200 200 200 200
				200 200 200 200 200 200 200 200 200 200 200 200 200 200 200 200 200 200
				200 200 200 200 200 200 200 200 200 200 200 200 200 200 200 200 200 200
				200 200 200 200 200 200 200 200 200 200 200 200 200 200 200 200 200 200
				200 200 200 200 200 200 200 200 200 200 200 200 200 200 200 200 200 200
				200 200 200 200 200 200 200 200 200 200 200 200 200 200 200 200 200 200
				200 200 200 200 200 200 200 200 200 200 200 200 200 200 200 200 200 200
				200 200 200 200 200 200 200 200 200 200 200 200 200 200 200 200 200 200
				200 200 200 200 200 200 200 200 200 200 200 200 200 200 200 200 200 200
				200 200 200 200 200 200 200 200 200 200 200 200 200 200 200 200 200 200
				200 200 200 200 200 200 200 200 200 200 200 200 200 200 200 200 200 200
				200 200 200 200 200 200 200 200 200 200 200 200 200 200 200 200 200 200
				200 200 200 200 200 200 200 200 200 200 200 200 200 200 200 200 200 200
				200 200 200 200 200 200 200 200 200 200 200 200 200 200 200 200 200 200
				200 200 200 200 200 200 200 200 200 200 200 200 200 200 200 200 200 200
				200 200 200 200 200 200 200 200 200 200 200 200 200 200 200 200 200 200
				200 200 200 200 200 200 200 200 200 200 200 200 200 200 200 200 200 200
				200 200 200 200 200 200 200 200 200 200 200 200 200 200 200 200 200 200
				200 200 200 200 200 200 200 200 200 200 200 200 200 200 200 200 200 200
				200 200 200 200 200 200 200 200 200 200 200 200 200 200 200 200 200 200
				200 200 200 200 200 200 200 200 200 200 200 200 200 200 200 200 200 200
				200 200 200 200 200 200 200 200 200 200 200 200 200 200 200 200 200 200
				200 200 200 200 200 200 200 200 200 200 200 200 200 200 200 200 200 200
				200 200 200 200 200 200 200 200 200 200 200 200 200 200 200 200 200 200
				200 200 200 200 200 200 200 200 200 200 200 200 200 200 200 200 200 200
				200 200 200 200 200 200 200 200 200 200 200 200 200 200 200 200 200 200
				200 200 200 200 200 200 200 200 200 200 200 200 200 200 200 200 200 200
				>;

			PS_Config_Lmt_LPWG_Diff_P = <
				65535 150 150 150 150 150 150 150 65535 65535 150 150 150 150 150 150 150 65535
				150 150 150 150 150 150    150    150    150    150    150    150 150 150 150 150 150 150
				150 150 150 150 150 150    150    150    150    150    150    150 150 150 150 150 150 150
				150 150 150 150 150 150    150    150    150    150    150    150 150 150 150 150 150 150
				150 150 150 150 150 150    150    150    150    150    150    150 150 150 150 150 150 150
				150 150 150 150 150 150    150    150    150    150    150    150 150 150 150 150 150 150
				150 150 150 150 150 150    150    150    150    150    150    150 150 150 150 150 150 150
				150 150 150 150 150 150    150    150    150    150    150    150 150 150 150 150 150 150
				150 150 150 150 150 150    150    150    150    150    150    150 150 150 150 150 150 150
				150 150 150 150 150 150    150    150    150    150    150    150 150 150 150 150 150 150
				150 150 150 150 150 150    150    150    150    150    150    150 150 150 150 150 150 150
				150 150 150 150 150 150    150    150    150    150    150    150 150 150 150 150 150 150
				150 150 150 150 150 150    150    150    150    150    150    150 150 150 150 150 150 150
				150 150 150 150 150 150    150    150    150    150    150    150 150 150 150 150 150 150
				150 150 150 150 150 150    150    150    150    150    150    150 150 150 150 150 150 150
				150 150 150 150 150 150    150    150    150    150    150    150 150 150 150 150 150 150
				150 150 150 150 150 150    150    150    150    150    150    150 150 150 150 150 150 150
				150 150 150 150 150 150    150    150    150    150    150    150 150 150 150 150 150 150
				150 150 150 150 150 150    150    150    150    150    150    150 150 150 150 150 150 150
				150 150 150 150 150 150    150    150    150    150    150    150 150 150 150 150 150 150
				150 150 150 150 150 150    150    150    150    150    150    150 150 150 150 150 150 150
				150 150 150 150 150 150    150    150    150    150    150    150 150 150 150 150 150 150
				150 150 150 150 150 150    150    150    150    150    150    150 150 150 150 150 150 150
				150 150 150 150 150 150    150    150    150    150    150    150 150 150 150 150 150 150
				150 150 150 150 150 150    150    150    150    150    150    150 150 150 150 150 150 150
				150 150 150 150 150 150    150    150    150    150    150    150 150 150 150 150 150 150
				150 150 150 150 150 150    150    150    150    150    150    150 150 150 150 150 150 150
				150 150 150 150 150 150    150    150    150    150    150    150 150 150 150 150 150 150
				150 150 150 150 150 150    150    150    150    150    150    150 150 150 150 150 150 150
				150 150 150 150 150 150    150    150    150    150    150    150 150 150 150 150 150 150
				150 150 150 150 150 150    150    150    150    150    150    150 150 150 150 150 150 150
				150 150 150 150 150 150    150    150    150    150    150    150 150 150 150 150 150 150
				>;

			PS_Config_Lmt_LPWG_Diff_N = <
				(-65535) (-80) (-80) (-80) (-80) (-80) (-80) (-80) (-65535) (-65535) (-80) (-80) (-80) (-80) (-80) (-80) (-80) (-65535)
				(-80) (-80) (-80) (-80) (-80) (-80)    (-80)    (-80)    (-80)    (-80)    (-80)    (-80) (-80) (-80) (-80) (-80) (-80) (-80)
				(-80) (-80) (-80) (-80) (-80) (-80)    (-80)    (-80)    (-80)    (-80)    (-80)    (-80) (-80) (-80) (-80) (-80) (-80) (-80)
				(-80) (-80) (-80) (-80) (-80) (-80)    (-80)    (-80)    (-80)    (-80)    (-80)    (-80) (-80) (-80) (-80) (-80) (-80) (-80)
				(-80) (-80) (-80) (-80) (-80) (-80)    (-80)    (-80)    (-80)    (-80)    (-80)    (-80) (-80) (-80) (-80) (-80) (-80) (-80)
				(-80) (-80) (-80) (-80) (-80) (-80)    (-80)    (-80)    (-80)    (-80)    (-80)    (-80) (-80) (-80) (-80) (-80) (-80) (-80)
				(-80) (-80) (-80) (-80) (-80) (-80)    (-80)    (-80)    (-80)    (-80)    (-80)    (-80) (-80) (-80) (-80) (-80) (-80) (-80)
				(-80) (-80) (-80) (-80) (-80) (-80)    (-80)    (-80)    (-80)    (-80)    (-80)    (-80) (-80) (-80) (-80) (-80) (-80) (-80)
				(-80) (-80) (-80) (-80) (-80) (-80)    (-80)    (-80)    (-80)    (-80)    (-80)    (-80) (-80) (-80) (-80) (-80) (-80) (-80)
				(-80) (-80) (-80) (-80) (-80) (-80)    (-80)    (-80)    (-80)    (-80)    (-80)    (-80) (-80) (-80) (-80) (-80) (-80) (-80)
				(-80) (-80) (-80) (-80) (-80) (-80)    (-80)    (-80)    (-80)    (-80)    (-80)    (-80) (-80) (-80) (-80) (-80) (-80) (-80)
				(-80) (-80) (-80) (-80) (-80) (-80)    (-80)    (-80)    (-80)    (-80)    (-80)    (-80) (-80) (-80) (-80) (-80) (-80) (-80)
				(-80) (-80) (-80) (-80) (-80) (-80)    (-80)    (-80)    (-80)    (-80)    (-80)    (-80) (-80) (-80) (-80) (-80) (-80) (-80)
				(-80) (-80) (-80) (-80) (-80) (-80)    (-80)    (-80)    (-80)    (-80)    (-80)    (-80) (-80) (-80) (-80) (-80) (-80) (-80)
				(-80) (-80) (-80) (-80) (-80) (-80)    (-80)    (-80)    (-80)    (-80)    (-80)    (-80) (-80) (-80) (-80) (-80) (-80) (-80)
				(-80) (-80) (-80) (-80) (-80) (-80)    (-80)    (-80)    (-80)    (-80)    (-80)    (-80) (-80) (-80) (-80) (-80) (-80) (-80)
				(-80) (-80) (-80) (-80) (-80) (-80)    (-80)    (-80)    (-80)    (-80)    (-80)    (-80) (-80) (-80) (-80) (-80) (-80) (-80)
				(-80) (-80) (-80) (-80) (-80) (-80)    (-80)    (-80)    (-80)    (-80)    (-80)    (-80) (-80) (-80) (-80) (-80) (-80) (-80)
				(-80) (-80) (-80) (-80) (-80) (-80)    (-80)    (-80)    (-80)    (-80)    (-80)    (-80) (-80) (-80) (-80) (-80) (-80) (-80)
				(-80) (-80) (-80) (-80) (-80) (-80)    (-80)    (-80)    (-80)    (-80)    (-80)    (-80) (-80) (-80) (-80) (-80) (-80) (-80)
				(-80) (-80) (-80) (-80) (-80) (-80)    (-80)    (-80)    (-80)    (-80)    (-80)    (-80) (-80) (-80) (-80) (-80) (-80) (-80)
				(-80) (-80) (-80) (-80) (-80) (-80)    (-80)    (-80)    (-80)    (-80)    (-80)    (-80) (-80) (-80) (-80) (-80) (-80) (-80)
				(-80) (-80) (-80) (-80) (-80) (-80)    (-80)    (-80)    (-80)    (-80)    (-80)    (-80) (-80) (-80) (-80) (-80) (-80) (-80)
				(-80) (-80) (-80) (-80) (-80) (-80)    (-80)    (-80)    (-80)    (-80)    (-80)    (-80) (-80) (-80) (-80) (-80) (-80) (-80)
				(-80) (-80) (-80) (-80) (-80) (-80)    (-80)    (-80)    (-80)    (-80)    (-80)    (-80) (-80) (-80) (-80) (-80) (-80) (-80)
				(-80) (-80) (-80) (-80) (-80) (-80)    (-80)    (-80)    (-80)    (-80)    (-80)    (-80) (-80) (-80) (-80) (-80) (-80) (-80)
				(-80) (-80) (-80) (-80) (-80) (-80)    (-80)    (-80)    (-80)    (-80)    (-80)    (-80) (-80) (-80) (-80) (-80) (-80) (-80)
				(-80) (-80) (-80) (-80) (-80) (-80)    (-80)    (-80)    (-80)    (-80)    (-80)    (-80) (-80) (-80) (-80) (-80) (-80) (-80)
				(-80) (-80) (-80) (-80) (-80) (-80)    (-80)    (-80)    (-80)    (-80)    (-80)    (-80) (-80) (-80) (-80) (-80) (-80) (-80)
				(-80) (-80) (-80) (-80) (-80) (-80)    (-80)    (-80)    (-80)    (-80)    (-80)    (-80) (-80) (-80) (-80) (-80) (-80) (-80)
				(-80) (-80) (-80) (-80) (-80) (-80)    (-80)    (-80)    (-80)    (-80)    (-80)    (-80) (-80) (-80) (-80) (-80) (-80) (-80)
				(-80) (-80) (-80) (-80) (-80) (-80)    (-80)    (-80)    (-80)    (-80)    (-80)    (-80) (-80) (-80) (-80) (-80) (-80) (-80)
				>;
		};

		novatek-mp-criteria-skyw@1 {
			#address-cells = <1>;
			#size-cells = <0>;
			compatible = "novatek-mp-criteria-skyw";

			/* MP Config */
			IC_X_CFG_SIZE = <18>;
			IC_Y_CFG_SIZE = <32>;
			IC_KEY_CFG_SIZE = <4>;
			X_Channel = <18>;
			Y_Channel = <32>;
			AIN_X = <0 1 2 3 4 5 6 7 8 9 10 11 12 13 14 15 16 17>;
			AIN_Y = <0 1 2 3 4 5 6 7 8 9 10 11 12 13 14 15 16 17 18 19
								20 21 22 23 24 25 26 27 28 29 30 31>;
			AIN_KEY = <0 1 2 0xFF>;

			/* MP Criteria */
			PS_Config_Lmt_Short_Rawdata_P = <
				14008 14008 14008 14008 14008 14008 14008 14008 14008 14008 14008 14008 14008 14008 14008 14008 14008 14008
				14008 14008 14008 14008 14008 14008 14008 14008 14008 14008 14008 14008 14008 14008 14008 14008 14008 14008
				14008 14008 14008 14008 14008 14008 14008 14008 14008 14008 14008 14008 14008 14008 14008 14008 14008 14008
				14008 14008 14008 14008 14008 14008 14008 14008 14008 14008 14008 14008 14008 14008 14008 14008 14008 14008
				14008 14008 14008 14008 14008 14008 14008 14008 14008 14008 14008 14008 14008 14008 14008 14008 14008 14008
				14008 14008 14008 14008 14008 14008 14008 14008 14008 14008 14008 14008 14008 14008 14008 14008 14008 14008
				14008 14008 14008 14008 14008 14008 14008 14008 14008 14008 14008 14008 14008 14008 14008 14008 14008 14008
				14008 14008 14008 14008 14008 14008 14008 14008 14008 14008 14008 14008 14008 14008 14008 14008 14008 14008
				14008 14008 14008 14008 14008 14008 14008 14008 14008 14008 14008 14008 14008 14008 14008 14008 14008 14008
				14008 14008 14008 14008 14008 14008 14008 14008 14008 14008 14008 14008 14008 14008 14008 14008 14008 14008
				14008 14008 14008 14008 14008 14008 14008 14008 14008 14008 14008 14008 14008 14008 14008 14008 14008 14008
				14008 14008 14008 14008 14008 14008 14008 14008 14008 14008 14008 14008 14008 14008 14008 14008 14008 14008
				14008 14008 14008 14008 14008 14008 14008 14008 14008 14008 14008 14008 14008 14008 14008 14008 14008 14008
				14008 14008 14008 14008 14008 14008 14008 14008 14008 14008 14008 14008 14008 14008 14008 14008 14008 14008
				14008 14008 14008 14008 14008 14008 14008 14008 14008 14008 14008 14008 14008 14008 14008 14008 14008 14008
				14008 14008 14008 14008 14008 14008 14008 14008 14008 14008 14008 14008 14008 14008 14008 14008 14008 14008
				14008 14008 14008 14008 14008 14008 14008 14008 14008 14008 14008 14008 14008 14008 14008 14008 14008 14008
				14008 14008 14008 14008 14008 14008 14008 14008 14008 14008 14008 14008 14008 14008 14008 14008 14008 14008
				14008 14008 14008 14008 14008 14008 14008 14008 14008 14008 14008 14008 14008 14008 14008 14008 14008 14008
				14008 14008 14008 14008 14008 14008 14008 14008 14008 14008 14008 14008 14008 14008 14008 14008 14008 14008
				14008 14008 14008 14008 14008 14008 14008 14008 14008 14008 14008 14008 14008 14008 14008 14008 14008 14008
				14008 14008 14008 14008 14008 14008 14008 14008 14008 14008 14008 14008 14008 14008 14008 14008 14008 14008
				14008 14008 14008 14008 14008 14008 14008 14008 14008 14008 14008 14008 14008 14008 14008 14008 14008 14008
				14008 14008 14008 14008 14008 14008 14008 14008 14008 14008 14008 14008 14008 14008 14008 14008 14008 14008
				14008 14008 14008 14008 14008 14008 14008 14008 14008 14008 14008 14008 14008 14008 14008 14008 14008 14008
				14008 14008 14008 14008 14008 14008 14008 14008 14008 14008 14008 14008 14008 14008 14008 14008 14008 14008
				14008 14008 14008 14008 14008 14008 14008 14008 14008 14008 14008 14008 14008 14008 14008 14008 14008 14008
				14008 14008 14008 14008 14008 14008 14008 14008 14008 14008 14008 14008 14008 14008 14008 14008 14008 14008
				14008 14008 14008 14008 14008 14008 14008 14008 14008 14008 14008 14008 14008 14008 14008 14008 14008 14008
				14008 14008 14008 14008 14008 14008 14008 14008 14008 14008 14008 14008 14008 14008 14008 14008 14008 14008
				14008 14008 14008 14008 14008 14008 14008 14008 14008 14008 14008 14008 14008 14008 14008 14008 14008 14008
				14008 14008 14008 14008 14008 14008 14008 14008 14008 14008 14008 14008 14008 14008 14008 14008 14008 14008
				>;

			PS_Config_Lmt_Short_Rawdata_N = <
				11376 11376 11376 11376 11376 11376 11376 11376 11376 11376 11376 11376 11376 11376 11376 11376 11376 11376
				11376 11376 11376 11376 11376 11376 11376 11376 11376 11376 11376 11376 11376 11376 11376 11376 11376 11376
				11376 11376 11376 11376 11376 11376 11376 11376 11376 11376 11376 11376 11376 11376 11376 11376 11376 11376
				11376 11376 11376 11376 11376 11376 11376 11376 11376 11376 11376 11376 11376 11376 11376 11376 11376 11376
				11376 11376 11376 11376 11376 11376 11376 11376 11376 11376 11376 11376 11376 11376 11376 11376 11376 11376
				11376 11376 11376 11376 11376 11376 11376 11376 11376 11376 11376 11376 11376 11376 11376 11376 11376 11376
				11376 11376 11376 11376 11376 11376 11376 11376 11376 11376 11376 11376 11376 11376 11376 11376 11376 11376
				11376 11376 11376 11376 11376 11376 11376 11376 11376 11376 11376 11376 11376 11376 11376 11376 11376 11376
				11376 11376 11376 11376 11376 11376 11376 11376 11376 11376 11376 11376 11376 11376 11376 11376 11376 11376
				11376 11376 11376 11376 11376 11376 11376 11376 11376 11376 11376 11376 11376 11376 11376 11376 11376 11376
				11376 11376 11376 11376 11376 11376 11376 11376 11376 11376 11376 11376 11376 11376 11376 11376 11376 11376
				11376 11376 11376 11376 11376 11376 11376 11376 11376 11376 11376 11376 11376 11376 11376 11376 11376 11376
				11376 11376 11376 11376 11376 11376 11376 11376 11376 11376 11376 11376 11376 11376 11376 11376 11376 11376
				11376 11376 11376 11376 11376 11376 11376 11376 11376 11376 11376 11376 11376 11376 11376 11376 11376 11376
				11376 11376 11376 11376 11376 11376 11376 11376 11376 11376 11376 11376 11376 11376 11376 11376 11376 11376
				11376 11376 11376 11376 11376 11376 11376 11376 11376 11376 11376 11376 11376 11376 11376 11376 11376 11376
				11376 11376 11376 11376 11376 11376 11376 11376 11376 11376 11376 11376 11376 11376 11376 11376 11376 11376
				11376 11376 11376 11376 11376 11376 11376 11376 11376 11376 11376 11376 11376 11376 11376 11376 11376 11376
				11376 11376 11376 11376 11376 11376 11376 11376 11376 11376 11376 11376 11376 11376 11376 11376 11376 11376
				11376 11376 11376 11376 11376 11376 11376 11376 11376 11376 11376 11376 11376 11376 11376 11376 11376 11376
				11376 11376 11376 11376 11376 11376 11376 11376 11376 11376 11376 11376 11376 11376 11376 11376 11376 11376
				11376 11376 11376 11376 11376 11376 11376 11376 11376 11376 11376 11376 11376 11376 11376 11376 11376 11376
				11376 11376 11376 11376 11376 11376 11376 11376 11376 11376 11376 11376 11376 11376 11376 11376 11376 11376
				11376 11376 11376 11376 11376 11376 11376 11376 11376 11376 11376 11376 11376 11376 11376 11376 11376 11376
				11376 11376 11376 11376 11376 11376 11376 11376 11376 11376 11376 11376 11376 11376 11376 11376 11376 11376
				11376 11376 11376 11376 11376 11376 11376 11376 11376 11376 11376 11376 11376 11376 11376 11376 11376 11376
				11376 11376 11376 11376 11376 11376 11376 11376 11376 11376 11376 11376 11376 11376 11376 11376 11376 11376
				11376 11376 11376 11376 11376 11376 11376 11376 11376 11376 11376 11376 11376 11376 11376 11376 11376 11376
				11376 11376 11376 11376 11376 11376 11376 11376 11376 11376 11376 11376 11376 11376 11376 11376 11376 11376
				11376 11376 11376 11376 11376 11376 11376 11376 11376 11376 11376 11376 11376 11376 11376 11376 11376 11376
				11376 11376 11376 11376 11376 11376 11376 11376 11376 11376 11376 11376 11376 11376 11376 11376 11376 11376
				11376 11376 11376 11376 11376 11376 11376 11376 11376 11376 11376 11376 11376 11376 11376 11376 11376 11376
				>;

			PS_Config_Lmt_Open_Rawdata_P = <
				65535 2870 2966 2923 2957 2870 2916 2861 65535 65535 2958 2984 2971 2993 2921 2850 2786 65535
				2589 2622 2695 2670 2720 2687 2735 2701 2705 2777 2795 2800 2781 2772 2689 2604 2554 2495
				2607 2631 2707 2688 2734 2701 2742 2712 2741 2812 2799 2804 2790 2784 2700 2614 2564 2515
				2645 2669 2751 2731 2781 2753 2795 2755 2785 2866 2855 2867 2853 2849 2759 2672 2624 2568
				2712 2742 2828 2807 2850 2819 2865 2826 2858 2913 2901 2913 2893 2893 2812 2722 2669 2614
				2751 2784 2871 2857 2904 2876 2911 2877 2907 2977 2966 2975 2969 2966 2882 2786 2732 2677
				2749 2780 2893 2874 2921 2889 2927 2896 2930 2979 2965 2971 2963 2967 2884 2795 2719 2666
				2789 2820 2935 2928 2963 2938 2974 2944 2978 3023 3012 3019 3012 3012 2946 2853 2780 2719
				2850 2892 3008 2996 3039 3005 3048 3020 3051 3087 3078 3086 3070 3079 3004 2916 2838 2778
				2907 2946 3063 3062 3102 3077 3106 3079 3105 3139 3133 3141 3139 3141 3077 2981 2898 2828
				2912 2948 3067 3063 3110 3078 3112 3081 3106 3125 3121 3132 3127 3135 3074 2988 2901 2843
				2959 2996 3114 3113 3159 3129 3159 3131 3151 3186 3186 3195 3191 3197 3141 3052 2981 2909
				3031 3075 3198 3190 3245 3218 3252 3216 3239 3249 3256 3266 3264 3264 3212 3124 3051 2971
				3083 3125 3252 3256 3305 3272 3306 3271 3290 3306 3317 3325 3325 3328 3286 3193 3117 3033
				3100 3136 3264 3270 3318 3287 3320 3283 3298 3289 3302 3312 3313 3316 3282 3193 3121 3040
				3141 3182 3310 3321 3366 3337 3368 3332 3344 3347 3364 3374 3375 3376 3356 3267 3186 3109
				3212 3255 3374 3426 3487 3457 3487 3452 3444 3386 3407 3416 3418 3418 3416 3357 3285 3191
				3249 3293 3413 3460 3529 3497 3529 3492 3497 3447 3472 3482 3484 3483 3480 3437 3359 3279
				3330 3368 3497 3545 3625 3595 3630 3592 3592 3499 3522 3536 3533 3532 3525 3492 3406 3329
				3363 3402 3524 3567 3656 3622 3661 3619 3619 3568 3598 3607 3605 3602 3598 3569 3483 3410
				3416 3452 3567 3617 3698 3669 3737 3700 3700 3594 3618 3629 3592 3596 3594 3571 3491 3421
				3441 3478 3605 3634 3725 3691 3760 3719 3721 3656 3686 3694 3663 3663 3663 3659 3576 3499
				3537 3576 3703 3744 3839 3814 3876 3842 3834 3711 3745 3753 3722 3725 3722 3722 3636 3563
				3571 3602 3740 3771 3884 3848 3911 3873 3866 3784 3825 3830 3802 3807 3800 3812 3723 3648
				3636 3661 3785 3812 3923 3883 3945 3904 3897 3762 3799 3810 3781 3794 3784 3807 3725 3652
				3660 3690 3818 3839 3956 3914 3976 3931 3927 3838 3880 3891 3866 3875 3869 3892 3818 3750
				3761 3795 3926 3977 4103 4073 4108 4058 4049 3904 3945 3965 3960 3962 3947 3956 3885 3815
				3800 3829 3958 4003 4130 4093 4131 4078 4069 3976 4018 4039 4035 4038 4024 4034 3969 3893
				3838 3877 3996 4035 4151 4116 4149 4095 4086 3943 3976 4007 3996 4008 3991 4012 3956 3891
				3888 3906 4026 4053 4173 4134 4165 4108 4104 4012 4046 4078 4070 4081 4066 4088 4039 3985
				3308 4016 4139 4176 4294 4257 4286 4231 4221 4073 4105 4145 4134 4149 4130 4153 4107 3310
				3353 3939 4143 4172 4290 4259 4289 4226 4234 4157 4178 4219 4213 4235 4217 4239 4107 3416
				>;

			PS_Config_Lmt_Open_Rawdata_N = <
				0 1382 1428 1407 1424 1382 1404 1377 0 0 1424 1437 1431 1441 1407 1372 1342 0
				1247 1262 1297 1286 1310 1294 1317 1301 1303 1337 1346 1348 1339 1334 1295 1254 1230 1201
				1255 1267 1303 1294 1316 1301 1320 1306 1320 1354 1347 1350 1344 1340 1300 1258 1234 1211
				1273 1285 1325 1315 1339 1325 1346 1327 1341 1380 1375 1381 1373 1372 1329 1286 1264 1236
				1306 1320 1362 1351 1372 1357 1379 1360 1376 1403 1397 1403 1393 1393 1354 1310 1285 1258
				1325 1340 1383 1375 1398 1385 1401 1385 1399 1433 1428 1433 1429 1428 1388 1342 1316 1289
				1323 1338 1393 1384 1407 1391 1409 1394 1411 1435 1427 1431 1427 1429 1388 1346 1309 1284
				1343 1358 1413 1410 1427 1414 1432 1418 1434 1455 1450 1453 1450 1450 1418 1373 1338 1309
				1372 1392 1448 1442 1463 1447 1468 1454 1469 1487 1482 1486 1478 1483 1446 1404 1366 1338
				1399 1418 1475 1474 1494 1481 1496 1483 1495 1511 1509 1513 1511 1513 1481 1435 1396 1362
				1402 1420 1477 1475 1498 1482 1498 1483 1496 1505 1503 1508 1505 1509 1480 1438 1397 1369
				1425 1442 1500 1499 1521 1507 1521 1507 1517 1534 1534 1539 1537 1539 1513 1470 1435 1401
				1459 1481 1540 1536 1563 1550 1566 1548 1559 1565 1568 1572 1572 1572 1546 1504 1469 1431
				1485 1505 1566 1568 1591 1576 1592 1575 1584 1592 1597 1601 1601 1602 1582 1537 1501 1461
				1492 1510 1572 1574 1598 1583 1598 1581 1588 1583 1590 1594 1595 1596 1580 1537 1503 1464
				1513 1532 1594 1599 1620 1607 1622 1604 1610 1611 1620 1624 1625 1626 1616 1573 1534 1497
				1546 1567 1624 1650 1679 1665 1679 1662 1658 1630 1641 1645 1646 1646 1645 1617 1581 1537
				1565 1585 1643 1666 1699 1684 1699 1682 1684 1659 1672 1676 1678 1677 1676 1655 1617 1579
				1604 1622 1684 1707 1745 1731 1748 1730 1730 1685 1696 1702 1701 1700 1697 1682 1640 1603
				1619 1638 1697 1717 1760 1744 1763 1743 1743 1718 1732 1737 1736 1734 1732 1719 1677 1642
				1645 1662 1717 1741 1780 1767 1799 1782 1782 1730 1742 1747 1730 1732 1730 1719 1681 1647
				1657 1674 1736 1750 1793 1777 1810 1791 1791 1760 1775 1778 1763 1763 1763 1762 1722 1685
				1703 1722 1783 1802 1849 1836 1866 1850 1846 1787 1803 1807 1792 1793 1792 1792 1750 1715
				1719 1734 1801 1815 1870 1853 1883 1865 1862 1822 1841 1844 1830 1833 1830 1836 1793 1756
				1750 1763 1823 1836 1889 1869 1899 1880 1877 1812 1829 1834 1821 1827 1822 1833 1793 1758
				1762 1776 1838 1849 1905 1884 1914 1893 1891 1848 1868 1873 1862 1866 1863 1874 1838 1806
				1811 1827 1890 1915 1975 1961 1978 1954 1949 1880 1899 1909 1906 1908 1901 1905 1871 1837
				1830 1843 1906 1927 1988 1971 1989 1964 1959 1914 1934 1945 1943 1944 1938 1942 1911 1875
				1848 1867 1924 1943 1999 1982 1997 1971 1968 1899 1914 1929 1924 1930 1921 1932 1905 1873
				1872 1880 1938 1951 2009 1990 2005 1978 1976 1932 1948 1964 1960 1965 1958 1968 1945 1919
				1593 1934 1993 2010 2068 2049 2064 2037 2033 1961 1977 1996 1990 1997 1988 1999 1977 1594
				1615 1897 1995 2009 2066 2051 2065 2035 2038 2001 2012 2031 2029 2039 2031 2041 1977 1645
				>;

			PS_Config_Lmt_FW_Rawdata_P = <
				65535 924 922 919 924 921 919 924 65535 65535 927 924 926 926 924 922 926 65535
				926 929 927 930 929 927 926 924 924 924 926 926 927 926 926 924 921 922
				922 926 926 924 921 922 926 922 924 921 926 927 927 921 926 926 924 924
				926 922 926 922 921 924 922 924 924 927 926 926 922 924 927 924 926 922
				918 924 922 921 922 919 924 922 921 926 921 924 922 921 929 927 924 921
				922 924 926 924 927 926 926 926 922 927 921 922 927 929 929 926 921 922
				926 919 922 924 924 926 924 922 924 922 922 924 922 924 926 924 919 922
				929 919 922 924 921 926 924 927 929 926 924 924 926 927 926 922 921 926
				922 926 926 921 921 918 919 922 924 924 922 921 921 922 922 922 927 922
				921 926 924 924 926 926 927 922 921 924 924 924 927 927 924 924 922 921
				921 926 929 924 924 922 924 921 919 926 926 926 930 929 922 922 926 924
				924 927 926 926 926 919 921 921 921 922 927 926 926 926 921 926 922 926
				921 924 922 926 924 919 924 922 926 926 922 922 924 930 926 927 922 926
				926 922 924 922 924 926 926 926 922 922 926 926 921 929 930 924 922 922
				921 929 927 927 926 927 922 924 921 924 924 927 927 927 926 927 924 919
				919 926 926 926 922 921 918 918 926 927 922 924 922 926 926 924 924 924
				922 926 924 926 922 922 926 922 927 922 922 926 926 924 926 922 924 927
				922 929 930 926 930 932 930 927 927 926 926 926 926 929 922 926 926 926
				921 924 924 926 926 922 919 921 924 924 926 926 926 927 922 921 924 924
				926 927 927 926 926 924 921 924 926 926 924 926 926 926 926 924 927 924
				926 926 927 927 926 922 924 926 926 927 929 922 926 924 927 926 926 924
				922 927 924 924 926 926 926 924 926 927 927 930 926 922 921 924 927 929
				924 922 927 927 930 932 926 927 924 924 924 924 926 929 926 924 921 924
				924 924 927 924 924 921 924 926 926 929 926 924 927 926 922 924 926 921
				926 919 924 924 926 924 926 924 922 926 927 929 924 926 924 922 921 926
				922 929 926 926 927 926 922 926 919 921 924 927 924 926 929 927 929 924
				921 924 924 927 922 929 922 922 922 926 929 929 927 922 921 926 924 927
				922 924 926 922 922 922 921 922 922 926 922 924 930 924 924 927 926 921
				924 924 922 927 922 924 924 924 926 927 924 921 927 924 924 921 927 919
				924 924 924 921 927 921 922 927 919 919 926 924 922 924 922 929 927 927
				922 924 919 921 924 922 924 926 918 922 927 921 922 927 924 926 921 924
				924 922 924 922 922 926 926 924 924 924 924 922 922 924 924 926 929 926
				>;

			PS_Config_Lmt_FW_Rawdata_N = <
				0 276 276 275 276 275 275 276 0 0 277 276 276 276 276 276 276 0
				276 277 277 278 277 277 276 276 276 276 276 276 277 276 276 276 275 276
				276 276 276 276 275 276 276 276 276 275 276 277 277 275 276 276 276 276
				276 276 276 276 275 276 276 276 276 277 276 276 276 276 277 276 276 276
				274 276 276 275 276 275 276 276 275 276 275 276 276 275 277 277 276 275
				276 276 276 276 277 276 276 276 276 277 275 276 277 277 277 276 275 276
				276 275 276 276 276 276 276 276 276 276 276 276 276 276 276 276 275 276
				277 275 276 276 275 276 276 277 277 276 276 276 276 277 276 276 275 276
				276 276 276 275 275 274 275 276 276 276 276 275 275 276 276 276 277 276
				275 276 276 276 276 276 277 276 275 276 276 276 277 277 276 276 276 275
				275 276 277 276 276 276 276 275 275 276 276 276 278 277 276 276 276 276
				276 277 276 276 276 275 275 275 275 276 277 276 276 276 275 276 276 276
				275 276 276 276 276 275 276 276 276 276 276 276 276 278 276 277 276 276
				276 276 276 276 276 276 276 276 276 276 276 276 275 277 278 276 276 276
				275 277 277 277 276 277 276 276 275 276 276 277 277 277 276 277 276 275
				275 276 276 276 276 275 274 274 276 277 276 276 276 276 276 276 276 276
				276 276 276 276 276 276 276 276 277 276 276 276 276 276 276 276 276 277
				276 277 278 276 278 278 278 277 277 276 276 276 276 277 276 276 276 276
				275 276 276 276 276 276 275 275 276 276 276 276 276 277 276 275 276 276
				276 277 277 276 276 276 275 276 276 276 276 276 276 276 276 276 277 276
				276 276 277 277 276 276 276 276 276 277 277 276 276 276 277 276 276 276
				276 277 276 276 276 276 276 276 276 277 277 278 276 276 275 276 277 277
				276 276 277 277 278 278 276 277 276 276 276 276 276 277 276 276 275 276
				276 276 277 276 276 275 276 276 276 277 276 276 277 276 276 276 276 275
				276 275 276 276 276 276 276 276 276 276 277 277 276 276 276 276 275 276
				276 277 276 276 277 276 276 276 275 275 276 277 276 276 277 277 277 276
				275 276 276 277 276 277 276 276 276 276 277 277 277 276 275 276 276 277
				276 276 276 276 276 276 275 276 276 276 276 276 278 276 276 277 276 275
				276 276 276 277 276 276 276 276 276 277 276 275 277 276 276 275 277 275
				276 276 276 275 277 275 276 277 275 275 276 276 276 276 276 277 277 277
				276 276 275 275 276 276 276 276 274 276 277 275 276 277 276 276 275 276
				276 276 276 276 276 276 276 276 276 276 276 276 276 276 276 276 277 276
				>;

			PS_Config_Lmt_FW_CC_P = <
				65535 73 73 73 73 73 73 72 65535 65535 76 76 75 75 75 75 75 65535
				73 75 75 73 73 73 73 73 73 77 77 77 76 76 76 76 76 75
				72 73 73 73 73 73 73 72 73 76 76 76 75 75 75 73 73 73
				73 75 75 73 73 73 73 73 73 77 77 77 77 76 76 76 76 75
				72 73 73 73 73 72 72 72 72 76 76 76 75 75 75 73 73 73
				73 73 73 73 73 73 73 73 73 77 77 77 76 76 76 76 75 75
				72 73 73 73 73 72 72 72 72 76 76 76 75 75 75 75 73 73
				73 73 75 73 73 73 73 73 73 79 77 77 77 77 76 76 76 75
				72 72 72 72 72 72 72 72 72 76 76 76 75 75 75 75 73 73
				73 75 75 73 73 73 73 73 73 77 77 77 76 76 76 76 76 75
				72 73 73 73 73 73 72 72 72 76 76 76 75 75 75 75 75 73
				73 75 75 73 73 73 73 73 73 79 77 77 77 77 76 76 76 75
				72 73 73 73 72 72 72 72 72 76 76 76 76 75 75 75 75 73
				73 73 73 73 73 73 73 73 73 79 77 77 77 77 76 76 76 75
				72 73 73 73 73 72 72 72 72 77 76 76 76 76 75 75 75 73
				73 75 75 75 75 73 73 73 73 79 77 77 77 77 76 76 76 75
				72 72 72 72 72 72 72 72 70 75 75 75 75 73 73 73 73 72
				70 72 72 72 72 70 70 70 70 76 76 76 75 75 75 75 73 73
				72 72 72 72 72 72 72 72 72 76 75 75 75 75 73 73 73 72
				70 72 72 72 72 72 72 70 70 76 76 76 76 75 75 75 75 73
				72 72 72 72 72 72 72 72 72 76 76 76 75 75 75 75 73 73
				70 72 72 72 72 72 72 72 70 76 76 76 76 75 75 75 75 73
				72 73 72 73 72 72 72 72 72 76 76 76 76 75 75 75 75 73
				72 72 72 72 72 72 72 72 72 77 77 76 76 76 75 75 75 73
				72 73 73 73 72 72 72 72 72 76 76 76 75 75 75 75 75 73
				72 72 72 72 72 72 72 72 72 77 77 77 76 76 76 75 75 75
				73 73 73 73 73 73 73 73 73 77 77 76 76 76 75 75 75 73
				72 73 73 73 73 73 73 73 73 79 79 79 77 77 77 76 76 75
				73 75 75 75 75 75 73 75 75 79 77 77 77 76 76 76 76 75
				73 75 75 75 75 75 75 75 75 81 80 80 79 79 79 77 77 76
				76 76 76 77 76 77 77 77 77 83 81 81 80 80 79 79 77 76
				76 79 79 79 79 80 80 81 81 87 86 86 84 84 83 80 79 77
				>;

			PS_Config_Lmt_FW_CC_N = <
				0 33 33 33 33 33 33 32 0 0 34 34 33 33 33 33 33 0
				33 33 33 33 33 33 33 33 33 35 35 35 34 34 34 34 34 33
				32 33 33 33 33 33 33 32 33 34 34 34 33 33 33 33 33 33
				33 33 33 33 33 33 33 33 33 35 35 35 35 34 34 34 34 33
				32 33 33 33 33 32 32 32 32 34 34 34 33 33 33 33 33 33
				33 33 33 33 33 33 33 33 33 35 35 35 34 34 34 34 33 33
				32 33 33 33 33 32 32 32 32 34 34 34 33 33 33 33 33 33
				33 33 33 33 33 33 33 33 33 35 35 35 35 35 34 34 34 33
				32 32 32 32 32 32 32 32 32 34 34 34 33 33 33 33 33 33
				33 33 33 33 33 33 33 33 33 35 35 35 34 34 34 34 34 33
				32 33 33 33 33 33 32 32 32 34 34 34 33 33 33 33 33 33
				33 33 33 33 33 33 33 33 33 35 35 35 35 35 34 34 34 33
				32 33 33 33 32 32 32 32 32 34 34 34 34 33 33 33 33 33
				33 33 33 33 33 33 33 33 33 35 35 35 35 35 34 34 34 33
				32 33 33 33 33 32 32 32 32 35 34 34 34 34 33 33 33 33
				33 33 33 33 33 33 33 33 33 35 35 35 35 35 34 34 34 33
				32 32 32 32 32 32 32 32 32 33 33 33 33 33 33 33 33 32
				32 32 32 32 32 32 32 32 32 34 34 34 33 33 33 33 33 33
				32 32 32 32 32 32 32 32 32 34 33 33 33 33 33 33 33 32
				32 32 32 32 32 32 32 32 32 34 34 34 34 33 33 33 33 33
				32 32 32 32 32 32 32 32 32 34 34 34 33 33 33 33 33 33
				32 32 32 32 32 32 32 32 32 34 34 34 34 33 33 33 33 33
				32 33 32 33 32 32 32 32 32 34 34 34 34 33 33 33 33 33
				32 32 32 32 32 32 32 32 32 35 35 34 34 34 33 33 33 33
				32 33 33 33 32 32 32 32 32 34 34 34 33 33 33 33 33 33
				32 32 32 32 32 32 32 32 32 35 35 35 34 34 34 33 33 33
				33 33 33 33 33 33 33 33 33 35 35 34 34 34 33 33 33 33
				32 33 33 33 33 33 33 33 33 35 35 35 35 35 35 34 34 33
				33 33 33 33 33 33 33 33 33 35 35 35 35 34 34 34 34 33
				33 33 33 33 33 33 33 33 33 37 36 36 35 35 35 35 35 34
				34 34 34 35 34 35 35 35 35 37 37 37 36 36 35 35 35 34
				34 35 35 35 35 36 36 37 37 39 38 38 38 38 37 36 35 35
				>;

			PS_Config_Lmt_FW_Diff_P = <
				65535 50 50 50 50 50 50 50 65535 65535 50 50 50 50 50 50 50 65535
				50 50 50 50 50 50 50 50 50 50 50 50 50 50 50 50 50 50
				50 50 50 50 50 50 50 50 50 50 50 50 50 50 50 50 50 50
				50 50 50 50 50 50 50 50 50 50 50 50 50 50 50 50 50 50
				50 50 50 50 50 50 50 50 50 50 50 50 50 50 50 50 50 50
				50 50 50 50 50 50 50 50 50 50 50 50 50 50 50 50 50 50
				50 50 50 50 50 50 50 50 50 50 50 50 50 50 50 50 50 50
				50 50 50 50 50 50 50 50 50 50 50 50 50 50 50 50 50 50
				50 50 50 50 50 50 50 50 50 50 50 50 50 50 50 50 50 50
				50 50 50 50 50 50 50 50 50 50 50 50 50 50 50 50 50 50
				50 50 50 50 50 50 50 50 50 50 50 50 50 50 50 50 50 50
				50 50 50 50 50 50 50 50 50 50 50 50 50 50 50 50 50 50
				50 50 50 50 50 50 50 50 50 50 50 50 50 50 50 50 50 50
				50 50 50 50 50 50 50 50 50 50 50 50 50 50 50 50 50 50
				50 50 50 50 50 50 50 50 50 50 50 50 50 50 50 50 50 50
				50 50 50 50 50 50 50 50 50 50 50 50 50 50 50 50 50 50
				50 50 50 50 50 50 50 50 50 50 50 50 50 50 50 50 50 50
				50 50 50 50 50 50 50 50 50 50 50 50 50 50 50 50 50 50
				50 50 50 50 50 50 50 50 50 50 50 50 50 50 50 50 50 50
				50 50 50 50 50 50 50 50 50 50 50 50 50 50 50 50 50 50
				50 50 50 50 50 50 50 50 50 50 50 50 50 50 50 50 50 50
				50 50 50 50 50 50 50 50 50 50 50 50 50 50 50 50 50 50
				50 50 50 50 50 50 50 50 50 50 50 50 50 50 50 50 50 50
				50 50 50 50 50 50 50 50 50 50 50 50 50 50 50 50 50 50
				50 50 50 50 50 50 50 50 50 50 50 50 50 50 50 50 50 50
				50 50 50 50 50 50 50 50 50 50 50 50 50 50 50 50 50 50
				50 50 50 50 50 50 50 50 50 50 50 50 50 50 50 50 50 50
				50 50 50 50 50 50 50 50 50 50 50 50 50 50 50 50 50 50
				50 50 50 50 50 50 50 50 50 50 50 50 50 50 50 50 50 50
				50 50 50 50 50 50 50 50 50 50 50 50 50 50 50 50 50 50
				50 50 50 50 50 50 50 50 50 50 50 50 50 50 50 50 50 50
				50 50 50 50 50 50 50 50 50 50 50 50 50 50 50 50 50 50
				>;

			PS_Config_Lmt_FW_Diff_N = <
				(-65535) (-50) (-50) (-50) (-50) (-50) (-50) (-50) (-65535) (-65535) (-50) (-50) (-50) (-50) (-50) (-50) (-50) (-65535)
				(-50) (-50) (-50) (-50) (-50) (-50)    (-50)    (-50)    (-50)    (-50)    (-50)    (-50) (-50) (-50) (-50) (-50) (-50) (-50)
				(-50) (-50) (-50) (-50) (-50) (-50)    (-50)    (-50)    (-50)    (-50)    (-50)    (-50) (-50) (-50) (-50) (-50) (-50) (-50)
				(-50) (-50) (-50) (-50) (-50) (-50)    (-50)    (-50)    (-50)    (-50)    (-50)    (-50) (-50) (-50) (-50) (-50) (-50) (-50)
				(-50) (-50) (-50) (-50) (-50) (-50)    (-50)    (-50)    (-50)    (-50)    (-50)    (-50) (-50) (-50) (-50) (-50) (-50) (-50)
				(-50) (-50) (-50) (-50) (-50) (-50)    (-50)    (-50)    (-50)    (-50)    (-50)    (-50) (-50) (-50) (-50) (-50) (-50) (-50)
				(-50) (-50) (-50) (-50) (-50) (-50)    (-50)    (-50)    (-50)    (-50)    (-50)    (-50) (-50) (-50) (-50) (-50) (-50) (-50)
				(-50) (-50) (-50) (-50) (-50) (-50)    (-50)    (-50)    (-50)    (-50)    (-50)    (-50) (-50) (-50) (-50) (-50) (-50) (-50)
				(-50) (-50) (-50) (-50) (-50) (-50)    (-50)    (-50)    (-50)    (-50)    (-50)    (-50) (-50) (-50) (-50) (-50) (-50) (-50)
				(-50) (-50) (-50) (-50) (-50) (-50)    (-50)    (-50)    (-50)    (-50)    (-50)    (-50) (-50) (-50) (-50) (-50) (-50) (-50)
				(-50) (-50) (-50) (-50) (-50) (-50)    (-50)    (-50)    (-50)    (-50)    (-50)    (-50) (-50) (-50) (-50) (-50) (-50) (-50)
				(-50) (-50) (-50) (-50) (-50) (-50)    (-50)    (-50)    (-50)    (-50)    (-50)    (-50) (-50) (-50) (-50) (-50) (-50) (-50)
				(-50) (-50) (-50) (-50) (-50) (-50)    (-50)    (-50)    (-50)    (-50)    (-50)    (-50) (-50) (-50) (-50) (-50) (-50) (-50)
				(-50) (-50) (-50) (-50) (-50) (-50)    (-50)    (-50)    (-50)    (-50)    (-50)    (-50) (-50) (-50) (-50) (-50) (-50) (-50)
				(-50) (-50) (-50) (-50) (-50) (-50)    (-50)    (-50)    (-50)    (-50)    (-50)    (-50) (-50) (-50) (-50) (-50) (-50) (-50)
				(-50) (-50) (-50) (-50) (-50) (-50)    (-50)    (-50)    (-50)    (-50)    (-50)    (-50) (-50) (-50) (-50) (-50) (-50) (-50)
				(-50) (-50) (-50) (-50) (-50) (-50)    (-50)    (-50)    (-50)    (-50)    (-50)    (-50) (-50) (-50) (-50) (-50) (-50) (-50)
				(-50) (-50) (-50) (-50) (-50) (-50)    (-50)    (-50)    (-50)    (-50)    (-50)    (-50) (-50) (-50) (-50) (-50) (-50) (-50)
				(-50) (-50) (-50) (-50) (-50) (-50)    (-50)    (-50)    (-50)    (-50)    (-50)    (-50) (-50) (-50) (-50) (-50) (-50) (-50)
				(-50) (-50) (-50) (-50) (-50) (-50)    (-50)    (-50)    (-50)    (-50)    (-50)    (-50) (-50) (-50) (-50) (-50) (-50) (-50)
				(-50) (-50) (-50) (-50) (-50) (-50)    (-50)    (-50)    (-50)    (-50)    (-50)    (-50) (-50) (-50) (-50) (-50) (-50) (-50)
				(-50) (-50) (-50) (-50) (-50) (-50)    (-50)    (-50)    (-50)    (-50)    (-50)    (-50) (-50) (-50) (-50) (-50) (-50) (-50)
				(-50) (-50) (-50) (-50) (-50) (-50)    (-50)    (-50)    (-50)    (-50)    (-50)    (-50) (-50) (-50) (-50) (-50) (-50) (-50)
				(-50) (-50) (-50) (-50) (-50) (-50)    (-50)    (-50)    (-50)    (-50)    (-50)    (-50) (-50) (-50) (-50) (-50) (-50) (-50)
				(-50) (-50) (-50) (-50) (-50) (-50)    (-50)    (-50)    (-50)    (-50)    (-50)    (-50) (-50) (-50) (-50) (-50) (-50) (-50)
				(-50) (-50) (-50) (-50) (-50) (-50)    (-50)    (-50)    (-50)    (-50)    (-50)    (-50) (-50) (-50) (-50) (-50) (-50) (-50)
				(-50) (-50) (-50) (-50) (-50) (-50)    (-50)    (-50)    (-50)    (-50)    (-50)    (-50) (-50) (-50) (-50) (-50) (-50) (-50)
				(-50) (-50) (-50) (-50) (-50) (-50)    (-50)    (-50)    (-50)    (-50)    (-50)    (-50) (-50) (-50) (-50) (-50) (-50) (-50)
				(-50) (-50) (-50) (-50) (-50) (-50)    (-50)    (-50)    (-50)    (-50)    (-50)    (-50) (-50) (-50) (-50) (-50) (-50) (-50)
				(-50) (-50) (-50) (-50) (-50) (-50)    (-50)    (-50)    (-50)    (-50)    (-50)    (-50) (-50) (-50) (-50) (-50) (-50) (-50)
				(-50) (-50) (-50) (-50) (-50) (-50)    (-50)    (-50)    (-50)    (-50)    (-50)    (-50) (-50) (-50) (-50) (-50) (-50) (-50)
				(-50) (-50) (-50) (-50) (-50) (-50)    (-50)    (-50)    (-50)    (-50)    (-50)    (-50) (-50) (-50) (-50) (-50) (-50) (-50)
				>;

			PS_Config_Diff_Test_Frame = <50>;

			PS_Config_Lmt_LPWG_Rawdata_P = <
				65535 930 930 930 930 930 930 930 65535 65535 930 930 930 930 930 930 930 65535
				930 930 930 930 930 930 930 930 930 930 930 930 930 930 930 930 930 930
				930 930 930 930 930 930 930 930 930 930 930 930 930 930 930 930 930 930
				930 930 930 930 930 930 930 930 930 930 930 930 930 930 930 930 930 930
				930 930 930 930 930 930 930 930 930 930 930 930 930 930 930 930 930 930
				930 930 930 930 930 930 930 930 930 930 930 930 930 930 930 930 930 930
				930 930 930 930 930 930 930 930 930 930 930 930 930 930 930 930 930 930
				930 930 930 930 930 930 930 930 930 930 930 930 930 930 930 930 930 930
				930 930 930 930 930 930 930 930 930 930 930 930 930 930 930 930 930 930
				930 930 930 930 930 930 930 930 930 930 930 930 930 930 930 930 930 930
				930 930 930 930 930 930 930 930 930 930 930 930 930 930 930 930 930 930
				930 930 930 930 930 930 930 930 930 930 930 930 930 930 930 930 930 930
				930 930 930 930 930 930 930 930 930 930 930 930 930 930 930 930 930 930
				930 930 930 930 930 930 930 930 930 930 930 930 930 930 930 930 930 930
				930 930 930 930 930 930 930 930 930 930 930 930 930 930 930 930 930 930
				930 930 930 930 930 930 930 930 930 930 930 930 930 930 930 930 930 930
				930 930 930 930 930 930 930 930 930 930 930 930 930 930 930 930 930 930
				930 930 930 930 930 930 930 930 930 930 930 930 930 930 930 930 930 930
				930 930 930 930 930 930 930 930 930 930 930 930 930 930 930 930 930 930
				930 930 930 930 930 930 930 930 930 930 930 930 930 930 930 930 930 930
				930 930 930 930 930 930 930 930 930 930 930 930 930 930 930 930 930 930
				930 930 930 930 930 930 930 930 930 930 930 930 930 930 930 930 930 930
				930 930 930 930 930 930 930 930 930 930 930 930 930 930 930 930 930 930
				930 930 930 930 930 930 930 930 930 930 930 930 930 930 930 930 930 930
				930 930 930 930 930 930 930 930 930 930 930 930 930 930 930 930 930 930
				930 930 930 930 930 930 930 930 930 930 930 930 930 930 930 930 930 930
				930 930 930 930 930 930 930 930 930 930 930 930 930 930 930 930 930 930
				930 930 930 930 930 930 930 930 930 930 930 930 930 930 930 930 930 930
				930 930 930 930 930 930 930 930 930 930 930 930 930 930 930 930 930 930
				930 930 930 930 930 930 930 930 930 930 930 930 930 930 930 930 930 930
				930 930 930 930 930 930 930 930 930 930 930 930 930 930 930 930 930 930
				930 930 930 930 930 930 930 930 930 930 930 930 930 930 930 930 930 930
				>;

			PS_Config_Lmt_LPWG_Rawdata_N = <
				0 270 270 270 270 270 270 270 0 0 270 270 270 270 270 270 270 0
				270 270 270 270 270 270 270 270 270 270 270 270 270 270 270 270 270 270
				270 270 270 270 270 270 270 270 270 270 270 270 270 270 270 270 270 270
				270 270 270 270 270 270 270 270 270 270 270 270 270 270 270 270 270 270
				270 270 270 270 270 270 270 270 270 270 270 270 270 270 270 270 270 270
				270 270 270 270 270 270 270 270 270 270 270 270 270 270 270 270 270 270
				270 270 270 270 270 270 270 270 270 270 270 270 270 270 270 270 270 270
				270 270 270 270 270 270 270 270 270 270 270 270 270 270 270 270 270 270
				270 270 270 270 270 270 270 270 270 270 270 270 270 270 270 270 270 270
				270 270 270 270 270 270 270 270 270 270 270 270 270 270 270 270 270 270
				270 270 270 270 270 270 270 270 270 270 270 270 270 270 270 270 270 270
				270 270 270 270 270 270 270 270 270 270 270 270 270 270 270 270 270 270
				270 270 270 270 270 270 270 270 270 270 270 270 270 270 270 270 270 270
				270 270 270 270 270 270 270 270 270 270 270 270 270 270 270 270 270 270
				270 270 270 270 270 270 270 270 270 270 270 270 270 270 270 270 270 270
				270 270 270 270 270 270 270 270 270 270 270 270 270 270 270 270 270 270
				270 270 270 270 270 270 270 270 270 270 270 270 270 270 270 270 270 270
				270 270 270 270 270 270 270 270 270 270 270 270 270 270 270 270 270 270
				270 270 270 270 270 270 270 270 270 270 270 270 270 270 270 270 270 270
				270 270 270 270 270 270 270 270 270 270 270 270 270 270 270 270 270 270
				270 270 270 270 270 270 270 270 270 270 270 270 270 270 270 270 270 270
				270 270 270 270 270 270 270 270 270 270 270 270 270 270 270 270 270 270
				270 270 270 270 270 270 270 270 270 270 270 270 270 270 270 270 270 270
				270 270 270 270 270 270 270 270 270 270 270 270 270 270 270 270 270 270
				270 270 270 270 270 270 270 270 270 270 270 270 270 270 270 270 270 270
				270 270 270 270 270 270 270 270 270 270 270 270 270 270 270 270 270 270
				270 270 270 270 270 270 270 270 270 270 270 270 270 270 270 270 270 270
				270 270 270 270 270 270 270 270 270 270 270 270 270 270 270 270 270 270
				270 270 270 270 270 270 270 270 270 270 270 270 270 270 270 270 270 270
				270 270 270 270 270 270 270 270 270 270 270 270 270 270 270 270 270 270
				270 270 270 270 270 270 270 270 270 270 270 270 270 270 270 270 270 270
				270 270 270 270 270 270 270 270 270 270 270 270 270 270 270 270 270 270
				>;

			PS_Config_Lmt_LPWG_Diff_P = <
				65535 60 60 60 60 60 60 60 65535 65535 60 60 60 60 60 60 60 65535
				60 60 60 60 60 60    60    60    60    60    60    60 60 60 60 60 60 60
				60 60 60 60 60 60    60    60    60    60    60    60 60 60 60 60 60 60
				60 60 60 60 60 60    60    60    60    60    60    60 60 60 60 60 60 60
				60 60 60 60 60 60    60    60    60    60    60    60 60 60 60 60 60 60
				60 60 60 60 60 60    60    60    60    60    60    60 60 60 60 60 60 60
				60 60 60 60 60 60    60    60    60    60    60    60 60 60 60 60 60 60
				60 60 60 60 60 60    60    60    60    60    60    60 60 60 60 60 60 60
				60 60 60 60 60 60    60    60    60    60    60    60 60 60 60 60 60 60
				60 60 60 60 60 60    60    60    60    60    60    60 60 60 60 60 60 60
				60 60 60 60 60 60    60    60    60    60    60    60 60 60 60 60 60 60
				60 60 60 60 60 60    60    60    60    60    60    60 60 60 60 60 60 60
				60 60 60 60 60 60    60    60    60    60    60    60 60 60 60 60 60 60
				60 60 60 60 60 60    60    60    60    60    60    60 60 60 60 60 60 60
				60 60 60 60 60 60    60    60    60    60    60    60 60 60 60 60 60 60
				60 60 60 60 60 60    60    60    60    60    60    60 60 60 60 60 60 60
				60 60 60 60 60 60    60    60    60    60    60    60 60 60 60 60 60 60
				60 60 60 60 60 60    60    60    60    60    60    60 60 60 60 60 60 60
				60 60 60 60 60 60    60    60    60    60    60    60 60 60 60 60 60 60
				60 60 60 60 60 60    60    60    60    60    60    60 60 60 60 60 60 60
				60 60 60 60 60 60    60    60    60    60    60    60 60 60 60 60 60 60
				60 60 60 60 60 60    60    60    60    60    60    60 60 60 60 60 60 60
				60 60 60 60 60 60    60    60    60    60    60    60 60 60 60 60 60 60
				60 60 60 60 60 60    60    60    60    60    60    60 60 60 60 60 60 60
				60 60 60 60 60 60    60    60    60    60    60    60 60 60 60 60 60 60
				60 60 60 60 60 60    60    60    60    60    60    60 60 60 60 60 60 60
				60 60 60 60 60 60    60    60    60    60    60    60 60 60 60 60 60 60
				60 60 60 60 60 60    60    60    60    60    60    60 60 60 60 60 60 60
				60 60 60 60 60 60    60    60    60    60    60    60 60 60 60 60 60 60
				60 60 60 60 60 60    60    60    60    60    60    60 60 60 60 60 60 60
				60 60 60 60 60 60    60    60    60    60    60    60 60 60 60 60 60 60
				60 60 60 60 60 60    60    60    60    60    60    60 60 60 60 60 60 60
				>;

			PS_Config_Lmt_LPWG_Diff_N = <
				(-65535) (-60) (-60) (-60) (-60) (-60) (-60) (-60) (-65535) (-65535) (-60) (-60) (-60) (-60) (-60) (-60) (-60) (-65535)
				(-60) (-60) (-60) (-60) (-60) (-60)    (-60)    (-60)    (-60)    (-60)    (-60)    (-60) (-60) (-60) (-60) (-60) (-60) (-60)
				(-60) (-60) (-60) (-60) (-60) (-60)    (-60)    (-60)    (-60)    (-60)    (-60)    (-60) (-60) (-60) (-60) (-60) (-60) (-60)
				(-60) (-60) (-60) (-60) (-60) (-60)    (-60)    (-60)    (-60)    (-60)    (-60)    (-60) (-60) (-60) (-60) (-60) (-60) (-60)
				(-60) (-60) (-60) (-60) (-60) (-60)    (-60)    (-60)    (-60)    (-60)    (-60)    (-60) (-60) (-60) (-60) (-60) (-60) (-60)
				(-60) (-60) (-60) (-60) (-60) (-60)    (-60)    (-60)    (-60)    (-60)    (-60)    (-60) (-60) (-60) (-60) (-60) (-60) (-60)
				(-60) (-60) (-60) (-60) (-60) (-60)    (-60)    (-60)    (-60)    (-60)    (-60)    (-60) (-60) (-60) (-60) (-60) (-60) (-60)
				(-60) (-60) (-60) (-60) (-60) (-60)    (-60)    (-60)    (-60)    (-60)    (-60)    (-60) (-60) (-60) (-60) (-60) (-60) (-60)
				(-60) (-60) (-60) (-60) (-60) (-60)    (-60)    (-60)    (-60)    (-60)    (-60)    (-60) (-60) (-60) (-60) (-60) (-60) (-60)
				(-60) (-60) (-60) (-60) (-60) (-60)    (-60)    (-60)    (-60)    (-60)    (-60)    (-60) (-60) (-60) (-60) (-60) (-60) (-60)
				(-60) (-60) (-60) (-60) (-60) (-60)    (-60)    (-60)    (-60)    (-60)    (-60)    (-60) (-60) (-60) (-60) (-60) (-60) (-60)
				(-60) (-60) (-60) (-60) (-60) (-60)    (-60)    (-60)    (-60)    (-60)    (-60)    (-60) (-60) (-60) (-60) (-60) (-60) (-60)
				(-60) (-60) (-60) (-60) (-60) (-60)    (-60)    (-60)    (-60)    (-60)    (-60)    (-60) (-60) (-60) (-60) (-60) (-60) (-60)
				(-60) (-60) (-60) (-60) (-60) (-60)    (-60)    (-60)    (-60)    (-60)    (-60)    (-60) (-60) (-60) (-60) (-60) (-60) (-60)
				(-60) (-60) (-60) (-60) (-60) (-60)    (-60)    (-60)    (-60)    (-60)    (-60)    (-60) (-60) (-60) (-60) (-60) (-60) (-60)
				(-60) (-60) (-60) (-60) (-60) (-60)    (-60)    (-60)    (-60)    (-60)    (-60)    (-60) (-60) (-60) (-60) (-60) (-60) (-60)
				(-60) (-60) (-60) (-60) (-60) (-60)    (-60)    (-60)    (-60)    (-60)    (-60)    (-60) (-60) (-60) (-60) (-60) (-60) (-60)
				(-60) (-60) (-60) (-60) (-60) (-60)    (-60)    (-60)    (-60)    (-60)    (-60)    (-60) (-60) (-60) (-60) (-60) (-60) (-60)
				(-60) (-60) (-60) (-60) (-60) (-60)    (-60)    (-60)    (-60)    (-60)    (-60)    (-60) (-60) (-60) (-60) (-60) (-60) (-60)
				(-60) (-60) (-60) (-60) (-60) (-60)    (-60)    (-60)    (-60)    (-60)    (-60)    (-60) (-60) (-60) (-60) (-60) (-60) (-60)
				(-60) (-60) (-60) (-60) (-60) (-60)    (-60)    (-60)    (-60)    (-60)    (-60)    (-60) (-60) (-60) (-60) (-60) (-60) (-60)
				(-60) (-60) (-60) (-60) (-60) (-60)    (-60)    (-60)    (-60)    (-60)    (-60)    (-60) (-60) (-60) (-60) (-60) (-60) (-60)
				(-60) (-60) (-60) (-60) (-60) (-60)    (-60)    (-60)    (-60)    (-60)    (-60)    (-60) (-60) (-60) (-60) (-60) (-60) (-60)
				(-60) (-60) (-60) (-60) (-60) (-60)    (-60)    (-60)    (-60)    (-60)    (-60)    (-60) (-60) (-60) (-60) (-60) (-60) (-60)
				(-60) (-60) (-60) (-60) (-60) (-60)    (-60)    (-60)    (-60)    (-60)    (-60)    (-60) (-60) (-60) (-60) (-60) (-60) (-60)
				(-60) (-60) (-60) (-60) (-60) (-60)    (-60)    (-60)    (-60)    (-60)    (-60)    (-60) (-60) (-60) (-60) (-60) (-60) (-60)
				(-60) (-60) (-60) (-60) (-60) (-60)    (-60)    (-60)    (-60)    (-60)    (-60)    (-60) (-60) (-60) (-60) (-60) (-60) (-60)
				(-60) (-60) (-60) (-60) (-60) (-60)    (-60)    (-60)    (-60)    (-60)    (-60)    (-60) (-60) (-60) (-60) (-60) (-60) (-60)
				(-60) (-60) (-60) (-60) (-60) (-60)    (-60)    (-60)    (-60)    (-60)    (-60)    (-60) (-60) (-60) (-60) (-60) (-60) (-60)
				(-60) (-60) (-60) (-60) (-60) (-60)    (-60)    (-60)    (-60)    (-60)    (-60)    (-60) (-60) (-60) (-60) (-60) (-60) (-60)
				(-60) (-60) (-60) (-60) (-60) (-60)    (-60)    (-60)    (-60)    (-60)    (-60)    (-60) (-60) (-60) (-60) (-60) (-60) (-60)
				(-60) (-60) (-60) (-60) (-60) (-60)    (-60)    (-60)    (-60)    (-60)    (-60)    (-60) (-60) (-60) (-60) (-60) (-60) (-60)
				>;
		};
	};
};
//#endif

&i2c0 {
	status = "disable";
};

/*SPI touch end*/
//#endif

/* CONSYS GPIO standardization */
&pio {
	consys_pins_default: consys_default {
	};
	gpslna_pins_init: gpslna@0 {
		pins_cmd_dat {
			pinmux = <PINMUX_GPIO91__FUNC_GPIO91>;
			slew-rate = <0>;
			bias-disable;
			output-low;
		};
	};
	gpslna_pins_oh: gpslna@1 {
		pins_cmd_dat {
			pinmux = <PINMUX_GPIO91__FUNC_GPIO91>;
			slew-rate = <1>;
			output-high;
		};
	};
	gpslna_pins_ol: gpslna@2 {
		pins_cmd_dat {
			pinmux = <PINMUX_GPIO91__FUNC_GPIO91>;
			slew-rate = <1>;
			output-low;
		};
	};
};
&consys {
	pinctrl-names = "default", "gps_lna_state_init",
		"gps_lna_state_oh", "gps_lna_state_ol";
	pinctrl-0 = <&consys_pins_default>;
	pinctrl-1 = <&gpslna_pins_init>;
	pinctrl-2 = <&gpslna_pins_oh>;
	pinctrl-3 = <&gpslna_pins_ol>;
	status = "okay";
};
/* CONSYS end */

/* accdet start */
&accdet {
	//Gong.Chen@ODM_WT.mm.audiodriver.machine.1673576, 2018/12/03, Modify for hp mic vol 2.7V
	accdet-mic-vol = <7>;
	headset-mode-setting = <0x500 0x500 1 0x1f0 0x800 0x800 0x20 0x44>;
	accdet-plugout-debounce = <1>;
	accdet-mic-mode = <1>;
	headset-eint-level-pol = <8>;
	//Gong.Chen@ODM_WT.mm.audiodriver.machine.1788540, 2019/01/09, Modify for meizu EP2x headset
	headset-three-key-threshold = <0 80 190 400>;
	headset-three-key-threshold-CDD = <0 121 192 600>;
	headset-four-key-threshold = <0 58 121 192 400>;
	pinctrl-names = "default", "state_eint_as_int";
	pinctrl-0 = <&accdet_pins_default>;
	pinctrl-1 = <&accdet_pins_eint_as_int>;
	status = "okay";
};
&pio {
	accdet_pins_default: accdetdefault {
	};
	accdet_pins_eint_as_int: accdeteint@0 {
		pins_cmd_dat {
			pinmux = <PINMUX_GPIO9__FUNC_GPIO9>;
			slew-rate = <0>;
			bias-disable;
		};
	};
};
/* accdet end */

//#ifdef ODM_WT_EDIT
//#Feng.Zhao@ODM_WT.BSP.Fingerprint.Basic, 2018/10/04, Modify for Fingerprint bringup
/* FINGERPRINT start */
/*&spi0 {
	#address-cells = <1>;
	#size-cells = <0>;
	fingerprint@0 {
		compatible = "goodix,goodix-fp";
		reg = <0>;
		spi-max-frequency = <8000000>;
		netlink-event = <30>;
		status = "okay";
	};
};

&goodix_fp {
	pinctrl-names = "default", "reset_high", "reset_low";
	pinctrl-0 = <&fingerprint_default>;
	pinctrl-1 = <&fingerprint_reset_high>;
	pinctrl-2 = <&fingerprint_reset_low>;
	status = "okay";
};

&pio {
	fingerprint_default: state_default {
	};
	fingerprint_reset_high: state_reset_high {
		pins_cmd_dat {
			pinmux = <PINMUX_GPIO172__FUNC_GPIO172>;
			slew-rate = <1>;
			output-high;
		};
	};
	fingerprint_reset_low: state_reset_low {
		pins_cmd_dat {
			pinmux = <PINMUX_GPIO172__FUNC_GPIO172>;
			slew-rate = <1>;
			output-low;
		};
	};
};*/

&spi1 {
	#address-cells = <1>;
	#size-cells = <0>;

	finger_fp@0 {
		compatible = "mediatek,fingerspi-fp";
		reg = <0>;
		spi-id = <1>;
		spi-irq = <5>;
		spi-reg = <11010000>;
		spi-max-frequency = <8000000>;
		avdd-gpios = <&pio 153 0x1>;
		#netlink-event = <30>;
		vmch-supply = <&mt_pmic_vmch_ldo_reg>;
		status = "okay";
	};
};

&eint_fp_n {
	pinctrl-names = "default", "rst-high", "rst-low", "power_on", "power_off",
	                "irq-init", "spi-default";
	pinctrl-0 = <&fp_default>;
	pinctrl-1 = <&fp_rst_high>;
	pinctrl-2 = <&fp_rst_low>;
	pinctrl-3 = <&fp_power_on>;
	pinctrl-4 = <&fp_power_off>;
	pinctrl-5 = <&fp_irq>;
	pinctrl-6 = <&fingerprint_pins_default>;
	status = "okay";
};

&pio {
	fp_default: fpdefault {
	};

	fp_rst_high: state_reset_high {
		pins_cmd_dat {
			pinmux = <PINMUX_GPIO171__FUNC_GPIO171>;
			slew-rate = <1>;
			output-high;
		};
	};

	fp_rst_low: state_reset_low {
		pins_cmd_dat {
			pinmux = <PINMUX_GPIO171__FUNC_GPIO171>;
			slew-rate = <1>;
			output-low;
		};
	};

	fp_power_on: state_power_on {
		pins_cmd_dat {
			pinmux = <PINMUX_GPIO153__FUNC_GPIO153>;
			slew-rate = <1>;
			output-high;
		};
	};

	fp_power_off: state_power_off {
		pins_cmd_dat {
			pinmux = <PINMUX_GPIO153__FUNC_GPIO153>;
			slew-rate = <1>;
			output-low;
		};
	};

	fp_irq: fp_eint@5 {
		pins_cmd_dat {
			pinmux = <PINMUX_GPIO5__FUNC_GPIO5>;
			slew-rate = <0>;
			bias-disable;
		};
	};
	fingerprint_pins_default: fp_default {
		pins_cmd_dat {
			pinmux = <PINMUX_GPIO26__FUNC_SPI1_A_CSB>;
			slew-rate = <1>;
			bias-pull-up;
		};

		pins_cmd2_dat {
			pinmux = <PINMUX_GPIO28__FUNC_SPI1_A_CLK>;
			slew-rate = <1>;
			bias-pull-down;
		};

		pins_cmd3_dat {
			pinmux = <PINMUX_GPIO25__FUNC_SPI1_A_MI>;
			slew-rate = <0>;
			bias-pull-down;
		};

		pins_cmd4_dat {
			pinmux = <PINMUX_GPIO27__FUNC_SPI1_A_MO>;
			slew-rate = <1>;
			bias-pull-down;
		};
	};
};


/* FINGERPRINT end */
//#endif

/* IRTX GPIO end */
&irtx_pwm {
	pinctrl-names = "irtx_gpio_led_default", "irtx_gpio_led_set";
	pinctrl-0 = <&irtx_gpio_led_default>;
	pinctrl-1 = <&irtx_gpio_led_set>;
	status = "okay";
};
&pio {
	irtx_gpio_led_default:irtx_gpio_led_def@gpio90 {
		pins_cmd_dat {
			pinmux = <PINMUX_GPIO90__FUNC_GPIO90>;
			slew-rate = <1>;
			bias-disable;
			output-low;
			input-schmitt-enable = <0>;
		};
	};

	irtx_gpio_led_set:irtx_gpio_led_set@gpio90 {
		pins_cmd_dat {
			pinmux = <PINMUX_GPIO90__FUNC_PWM0>;
			slew-rate = <1>;
			output-high;
		};
	};
};
/* IRTX GPIO Settings -End */

/* AUDIO GPIO standardization */
&audgpio {
	//Gong.Chen@ODM_WT.mm.audiodriver.machine, 2018/10/02, Add for speaker
	pinctrl-names = "aud_clk_mosi_off",
			"aud_clk_mosi_on",
			"aud_clk_miso_off",
			"aud_clk_miso_on",
			"aud_dat_mosi_off",
			"aud_dat_mosi_on",
			"aud_dat_miso_off",
			"aud_dat_miso_on",
			"aud_smartpa_off",
			"aud_smartpa_on",
			"extamp-pulllow",
			"extamp-pullhigh";
	pinctrl-0 = <&aud_clk_mosi_off>;
	pinctrl-1 = <&aud_clk_mosi_on>;
	pinctrl-2 = <&aud_clk_miso_off>;
	pinctrl-3 = <&aud_clk_miso_on>;
	pinctrl-4 = <&aud_dat_mosi_off>;
	pinctrl-5 = <&aud_dat_mosi_on>;
	pinctrl-6 = <&aud_dat_miso_off>;
	pinctrl-7 = <&aud_dat_miso_on>;
	pinctrl-8 = <&aud_pins_smartpa_off>;
	pinctrl-9 = <&aud_pins_smartpa_on>;
	pinctrl-10 = <&aud_pins_extamp_off>;
	pinctrl-11 = <&aud_pins_extamp_on>;
	status = "okay";
};

&pio {
	aud_clk_mosi_off: aud_clk_mosi_off {
		pins_cmd0_dat {
			pinmux = <PINMUX_GPIO136__FUNC_GPIO136>;
		};
	};

	aud_clk_mosi_on: aud_clk_mosi_on {
		pins_cmd0_dat {
			pinmux = <PINMUX_GPIO136__FUNC_AUD_CLK_MOSI>;
		};
	};

	aud_clk_miso_off: aud_clk_miso_off {
		pins_cmd0_dat {
			pinmux = <PINMUX_GPIO140__FUNC_GPIO140>;
		};
	};

	aud_clk_miso_on: aud_clk_miso_on {
		pins_cmd0_dat {
			pinmux = <PINMUX_GPIO140__FUNC_AUD_CLK_MISO>;
		};
	};

	aud_dat_mosi_off: aud_dat_mosi_off {
		pins_cmd1_dat {
			pinmux = <PINMUX_GPIO138__FUNC_GPIO138>;
			input-enable;
			slew-rate = <0>;
			bias-disable;
		};
		pins_cmd2_dat {
			pinmux = <PINMUX_GPIO139__FUNC_GPIO139>;
			input-enable;
			slew-rate = <0>;
			bias-disable;
		};
	};

	aud_dat_mosi_on: aud_dat_mosi_on {
		pins_cmd1_dat {
			pinmux = <PINMUX_GPIO138__FUNC_AUD_DAT_MOSI0>;
		};
		pins_cmd2_dat {
			pinmux = <PINMUX_GPIO139__FUNC_AUD_DAT_MOSI1>;
		};
	};

	aud_dat_miso_off: aud_dat_miso_off {
		pins_cmd1_dat {
			pinmux = <PINMUX_GPIO142__FUNC_GPIO142>;
			input-enable;
			slew-rate = <0>;
			bias-disable;
		};
		pins_cmd2_dat {
			pinmux = <PINMUX_GPIO143__FUNC_GPIO143>;
			input-enable;
			slew-rate = <0>;
			bias-disable;
		};
	};

	aud_dat_miso_on: aud_dat_miso_on {
		pins_cmd1_dat {
			pinmux = <PINMUX_GPIO142__FUNC_AUD_DAT_MISO0>;
		};
		pins_cmd2_dat {
			pinmux = <PINMUX_GPIO143__FUNC_AUD_DAT_MISO1>;
		};
	};

	aud_pins_smartpa_off: aud_pins_smartpa_off {
		pins_cmd0_dat {
			pinmux = <PINMUX_GPIO17__FUNC_GPIO17>;
		};
		pins_cmd1_dat {
			pinmux = <PINMUX_GPIO18__FUNC_GPIO18>;
		};
		pins_cmd2_dat {
			pinmux = <PINMUX_GPIO19__FUNC_GPIO19>;
		};
		pins_cmd3_dat {
			pinmux = <PINMUX_GPIO20__FUNC_GPIO20>;
		};
	};

	aud_pins_smartpa_on: aud_pins_smartpa_on {
		pins_cmd0_dat {
			pinmux = <PINMUX_GPIO17__FUNC_I2S0_DI>;
		};
		pins_cmd1_dat {
			pinmux = <PINMUX_GPIO18__FUNC_I2S3_BCK>;
		};
		pins_cmd2_dat {
			pinmux = <PINMUX_GPIO19__FUNC_I2S3_LRCK>;
		};
		pins_cmd3_dat {
			pinmux = <PINMUX_GPIO20__FUNC_I2S3_DO>;
		};
	};

	//#ifdef ODM_WT_EDIT
	//Gong.Chen@ODM_WT.mm.audiodriver.machine, 2018/10/02, Add for speaker
	aud_pins_extamp_off: aud_pins_extamp_off {
		pins_cmd_dat {
			pinmux = <PINMUX_GPIO159__FUNC_GPIO159>;
			slew-rate = <1>;
			output-low;
		};
	};

	aud_pins_extamp_on: aud_pins_extamp_on {
		pins_cmd_dat {
			pinmux = <PINMUX_GPIO159__FUNC_GPIO159>;
			slew-rate = <1>;
			output-high;
		};
	};
	//endif /* ODM_WT_EDIT */
};
/* AUDIO end */

&mt6370_pmu {
	mt6370,intr_gpio_num = <11>; /* direct defined GPIO num */
	mt6370,intr_gpio = <&pio 11 0x0>;
};

&mt6370_typec {
	mt6370pd,intr_gpio_num = <41>; /* direct defined GPIO num */
	mt6370pd,intr_gpio = <&pio 41 0x0>;
};

&i2c3 {
	rt9465@4b {
		compatible = "richtek,rt9465";
		reg = <0x4b>;
		status = "okay";
		rt,en_gpio_num = <176>;
		rt,en_gpio = <&pio 176 0x0>;
//Bin.Su@ODM_WT.BSP.TouchScreen, 2018/08/09, wrong gpio 23 dts for TouchScreen BringUp
		/*rt,intr_gpio_num = <23>;*//* direct defined GPIO num */
		/*rt,intr_gpio = <&pio 23 0x0>;*/
		interrupt-names = "wdtmri";
		charger_name = "secondary_chg";
		ichg = <1500000>; /* uA */
		mivr = <4500000>; /* uV */
		cv = <4550000>; /* uV */
		ieoc = <700000>; /* uA */
		safety_timer = <12>; /* hour */
		en_st; /* safety timer */
		/* en_te; */
		en_wdt;
	};
};

&pio {
	camera_pins_cam0_mclk_on: camera_pins_cam0_mclk_on {
		pins_cmd_dat {
			pinmux = <PINMUX_GPIO99__FUNC_CMMCLK0>;
		};
	};
	camera_pins_cam0_mclk_off: camera_pins_cam0_mclk_off {
		pins_cmd_dat {
			pinmux = <PINMUX_GPIO99__FUNC_GPIO99>;
		};
	};
	camera_pins_cam1_mclk_on: camera_pins_cam1_mclk_on {
		pins_cmd_dat {
			pinmux = <PINMUX_GPIO100__FUNC_CMMCLK1>;
		};
	};
	camera_pins_cam1_mclk_off: camera_pins_cam1_mclk_off {
		pins_cmd_dat {
			pinmux = <PINMUX_GPIO100__FUNC_GPIO100>;
		};
	};
	camera_pins_cam2_mclk_on: camera_pins_cam2_mclk_on {
		pins_cmd_dat {
			pinmux = <PINMUX_GPIO108__FUNC_CMMCLK2>;
		};
	};
	camera_pins_cam2_mclk_off: camera_pins_cam2_mclk_off {
		pins_cmd_dat {
			pinmux = <PINMUX_GPIO108__FUNC_GPIO108>;
		};
	};
	camera_pins_cam0_rst0: cam0@0 {
		pins_cmd_dat {
			pinmux = <PINMUX_GPIO101__FUNC_GPIO101>;
			slew-rate = <1>;
			output-low;
		};
	};
	camera_pins_cam0_rst1: cam0@1 {
		pins_cmd_dat {
			pinmux = <PINMUX_GPIO101__FUNC_GPIO101>;
			slew-rate = <1>;
			output-high;
		};
	};
	camera_pins_cam1_rst0: cam1@0 {
		pins_cmd_dat {
			pinmux = <PINMUX_GPIO102__FUNC_GPIO102>;
			slew-rate = <1>;
			output-low;
		};
	};
	camera_pins_cam1_rst1: cam1@1 {
		pins_cmd_dat {
			pinmux = <PINMUX_GPIO102__FUNC_GPIO102>;
			slew-rate = <1>;
			output-high;
		};
	};
/* Hanyue.Shao@Camera.Driver, 2019/01/09, add for control i2c power start */
	camera_pins_cam0_scl0: cam0@scl0 {
		pins_cmd_dat {
			pinmux = <PINMUX_GPIO103__FUNC_SCL2>;
			slew-rate = <0>;
			bias-pull-down;
		};
	};
	camera_pins_cam0_scl1: cam0@scl1 {
		pins_cmd_dat {
			pinmux = <PINMUX_GPIO103__FUNC_SCL2>;
			slew-rate = <0>;
			bias-pull-up;
		};
	};
	camera_pins_cam0_sda0: cam0@sda0 {
		pins_cmd_dat {
			pinmux = <PINMUX_GPIO104__FUNC_SDA2>;
			slew-rate = <0>;
			bias-pull-down;
		};
	};
	camera_pins_cam0_sda1: cam0@sda1 {
		pins_cmd_dat {
			pinmux = <PINMUX_GPIO104__FUNC_SDA2>;
			slew-rate = <0>;
			bias-pull-up;
		};
	};
/* Hanyue.Shao@Camera.Driver, 2019/01/09, add for control i2c power end */
	camera_pins_cam2_rst0: cam2@0 {
		pins_cmd_dat {
			pinmux = <PINMUX_GPIO109__FUNC_GPIO109>;
			slew-rate = <1>;
			output-low;
		};
	};
	camera_pins_cam2_rst1: cam2@1 {
		pins_cmd_dat {
			pinmux = <PINMUX_GPIO109__FUNC_GPIO109>;
			slew-rate = <1>;
			output-high;
		};
	};
	camera_pins_cam2_pnd0: cam2@2 {
		pins_cmd_dat {
			pinmux = <PINMUX_GPIO107__FUNC_GPIO107>;
			slew-rate = <1>;
			output-low;
		};
	};
	camera_pins_cam2_pnd1: cam2@3 {
		pins_cmd_dat {
			pinmux = <PINMUX_GPIO107__FUNC_GPIO107>;
			slew-rate = <1>;
			output-high;
		};
	};
	camera_pins_cam1_pnd0: cam1@2 {
		pins_cmd_dat {
			pinmux = <PINMUX_GPIO167__FUNC_GPIO167>;
			slew-rate = <1>;
			output-low;
		};
	};
	camera_pins_cam1_pnd1: cam1@3 {
		pins_cmd_dat {
			pinmux = <PINMUX_GPIO167__FUNC_GPIO167>;
			slew-rate = <1>;
			output-high;
		};
	};
	camera_pins_cam_ldo_rear_vcama_0: cam0@vcama0 {
		pins_cmd_dat {
			pinmux = <PINMUX_GPIO175__FUNC_GPIO175>;
			slew-rate = <1>;
			output-low;
		};
	};
	camera_pins_cam_ldo_sub_vcama_1: cam1@vcama1 {
		pins_cmd_dat {
			pinmux = <PINMUX_GPIO175__FUNC_GPIO175>;
			slew-rate = <1>;
			output-high;
		};
	};
	camera_pins_cam_ldo_sub_vcama_0: cam1@vcama0 {
		pins_cmd_dat {
			pinmux = <PINMUX_GPIO175__FUNC_GPIO175>;
			slew-rate = <1>;
			output-low;
		};
	};
	camera_pins_cam_ldo_rear_vcama_1: cam0@vcama1 {
		pins_cmd_dat {
			pinmux = <PINMUX_GPIO175__FUNC_GPIO175>;
			slew-rate = <1>;
			output-high;
		};
	};
	camera_pins_default: camdefault {
	};

};

&kd_camera_hw1 {
	camera,vcam_iic2_scl = <&pio 103 0>;
	camera,vcam_iic2_sda = <&pio 104 0>;
	camera,vcam_en = <&pio 177 0>;
	camera,vcam_id = <&pio 178 0>;
	pinctrl-names = "default",
			"cam0_rst0",
			"cam0_rst1",
			"cam1_rst0",
			"cam1_rst1",
/* Hanyue.Shao@Camera.Driver, 2019/01/09, add for control i2c power start */
			"cam0_scl0",
			"cam0_scl1",
			"cam0_sda0",
			"cam0_sda1",
/* Hanyue.Shao@Camera.Driver, 2019/01/09, add for control i2c power end */
			"cam1_pnd0",
			"cam1_pnd1",
			"cam2_rst0",
			"cam2_rst1",
			"cam2_pnd0",
			"cam2_pnd1",
			"cam0_vcama_on",
			"cam0_vcama_off",
			"cam1_vcama_on",
			"cam1_vcama_off",
			"cam0_mclk_on",
			"cam0_mclk_off",
			"cam1_mclk_on",
			"cam1_mclk_off",
			"cam2_mclk_on",
			"cam2_mclk_off";

	pinctrl-0 = <&camera_pins_default>;
	pinctrl-1 = <&camera_pins_cam0_rst0>;
	pinctrl-2 = <&camera_pins_cam0_rst1>;
	pinctrl-3 = <&camera_pins_cam1_rst0>;
	pinctrl-4 = <&camera_pins_cam1_rst1>;
/* Hanyue.Shao@Camera.Driver, 2019/01/09, add for control i2c power start */
	pinctrl-5 = <&camera_pins_cam0_scl0>;
	pinctrl-6 = <&camera_pins_cam0_scl1>;
	pinctrl-7 = <&camera_pins_cam0_sda0>;
	pinctrl-8 = <&camera_pins_cam0_sda1>;
/* Hanyue.Shao@Camera.Driver, 2019/01/09, add for control i2c power end */
	pinctrl-9 = <&camera_pins_cam1_pnd0>;
	pinctrl-10 = <&camera_pins_cam1_pnd1>;
	pinctrl-11 = <&camera_pins_cam2_rst0>;
	pinctrl-12 = <&camera_pins_cam2_rst1>;
	pinctrl-13 = <&camera_pins_cam2_pnd0>;
	pinctrl-14 = <&camera_pins_cam2_pnd1>;
	pinctrl-15 = <&camera_pins_cam_ldo_rear_vcama_1>;
	pinctrl-16 = <&camera_pins_cam_ldo_rear_vcama_0>;
	pinctrl-17 = <&camera_pins_cam_ldo_sub_vcama_1>;
	pinctrl-18 = <&camera_pins_cam_ldo_sub_vcama_0>;
	pinctrl-19 = <&camera_pins_cam0_mclk_on>;
	pinctrl-20 = <&camera_pins_cam0_mclk_off>;
	pinctrl-21 = <&camera_pins_cam1_mclk_on>;
	pinctrl-22 = <&camera_pins_cam1_mclk_off>;
	pinctrl-23 = <&camera_pins_cam2_mclk_on>;
	pinctrl-24 = <&camera_pins_cam2_mclk_off>;
	status = "okay";
};

&flashlights_oppo {
        pinctrl-names = "hwen_default","hwen_high","hwen_low";
        pinctrl-0 = <&flashlights_oppo_pins_hwen_default>;
        pinctrl-1 = <&flashlights_oppo_pins_hwen_high>;
        pinctrl-2 = <&flashlights_oppo_pins_hwen_low>;
        status = "okay";
};

&pio {
        flashlights_oppo_pins_hwen_default:hwen_default {
		};
        flashlights_oppo_pins_hwen_high: hwen_high {
                pins_cmd_dat {
                        pinmux = <PINMUX_GPIO152__FUNC_GPIO152>;
                        slew-rate = <1>;
                        output-high;
                };
        };
        flashlights_oppo_pins_hwen_low: hwen_low {
                pins_cmd_dat {
                        pinmux = <PINMUX_GPIO152__FUNC_GPIO152>;
                        slew-rate = <1>;
                        output-low;
                };
        };
};

//#ifdef ODM_WT_EDIT
//Yanchao.Hu@ODM_WT.BSP.Storage.Sdcard, 2018/09/28, Modify for sdcard irq trigger states
&msdc1 {
	cd_level = /bits/ 8 <MSDC_CD_HIGH>;

// Yanchao.Hu@ODM_WT.BSP.Storage.Sdcard, 2018/10/30, Add for T-card ldo	
	gpio_tf_ldo = <&pio 173 0>;
	
};
//#endif /*ODM_WT_EDIT*/

//#ifdef ODM_WT_EDIT
//Yanchao.Hu@ODM_WT.BSP.Storage.otg, 2018/11/16, Modify for summer otg_switch
&otg_iddig{
    pinctrl-names = "otg_pins_default", "otg_iddg_high",
        "otg_gpio_low";
    pinctrl-0 = <&otg_pins_default>;
    pinctrl-1 = <&otg_iddg_high>;
    pinctrl-2 = <&otg_gpio_low>;
    status = "okay";

};


&pio {
    otg_pins_default: otg_pins_default {
    };
    otg_iddg_high: otg_iddg_high {
        pins_cmd_dat {
            pinmux = <PINMUX_GPIO41__FUNC_IDDIG>;
        };
    };
    otg_gpio_low: otg_gpio_low {
        pins_cmd_dat {
            pinmux = <PINMUX_GPIO41__FUNC_GPIO41>;
            slew-rate = <1>;
            input-low;
        };
    };
};
//#endif /*ODM_WT_EDIT*/

/* #ifdef ODM_WT_EDIT */
/* Benzhong.Hou@ODM_WT.MM.Display.Lcd, 2018/10/08, LCD voltage control */
/* DISPSYS GPIO standardization */
&mtkfb {
        pinctrl-names = "lcm_rst_out0_gpio", "lcm_rst_out1_gpio", "lcd_bias_enp0_gpio", "lcd_bias_enp1_gpio",
			"lcd_bias_enn0_gpio", "lcd_bias_enn1_gpio", "lcd_vddio18_en0_gpio", "lcd_vddio18_en1_gpio";

	pinctrl-0 = <&mtkfb_pins_lcm_reset0>;
	pinctrl-1 = <&mtkfb_pins_lcm_reset1>;
	pinctrl-2 = <&mtkfb_pins_lcd_bias_enp0>;
	pinctrl-3 = <&mtkfb_pins_lcd_bias_enp1>;
	pinctrl-4 = <&mtkfb_pins_lcd_bias_enn0>;
	pinctrl-5 = <&mtkfb_pins_lcd_bias_enn1>;
	pinctrl-6 = <&mtkfb_pins_lcd_vddio18_en0>;
	pinctrl-7 = <&mtkfb_pins_lcd_vddio18_en1>;
        status = "okay";
};

&pio {
        mtkfb_pins_lcm_reset0: lcm_rst_out0_gpio {
                pins_cmd_dat {
                        pinmux = <PINMUX_GPIO45__FUNC_GPIO45>;
                        slew-rate = <1>;
                        output-low;
                };
        };
        mtkfb_pins_lcm_reset1: lcm_rst_out1_gpio {
                pins_cmd_dat {
                        pinmux = <PINMUX_GPIO45__FUNC_GPIO45>;
                        slew-rate = <1>;
                        output-high;
                };
        };

	mtkfb_pins_lcd_bias_enp0: lcd_bias_enp0_gpio {
                pins_cmd_dat {
                        pinmux = <PINMUX_GPIO150__FUNC_GPIO150>;
                        slew-rate = <1>;
                        output-low;
                };
        };
	mtkfb_pins_lcd_bias_enp1: lcd_bias_enp1_gpio {
                pins_cmd_dat {
                        pinmux = <PINMUX_GPIO150__FUNC_GPIO150>;
                        slew-rate = <1>;
                        output-high;
                };
        };

	mtkfb_pins_lcd_bias_enn0: lcd_bias_enn0_gpio {
                pins_cmd_dat {
                        pinmux = <PINMUX_GPIO151__FUNC_GPIO151>;
                        slew-rate = <1>;
                        output-low;
                };
        };
	mtkfb_pins_lcd_bias_enn1: lcd_bias_enn1_gpio {
                pins_cmd_dat {
                        pinmux = <PINMUX_GPIO151__FUNC_GPIO151>;
                        slew-rate = <1>;
                        output-high;
                };
        };

	mtkfb_pins_lcd_vddio18_en0: lcd_vddio18_en0_gpio {
                pins_cmd_dat {
                        pinmux = <PINMUX_GPIO170__FUNC_GPIO170>;
                        slew-rate = <1>;
                        output-low;
                };
        };
	mtkfb_pins_lcd_vddio18_en1: lcd_vddio18_en1_gpio {
                pins_cmd_dat {
                        pinmux = <PINMUX_GPIO170__FUNC_GPIO170>;
                        slew-rate = <1>;
                        output-high;
                };
        };
};
/* Benzhong.Hou@ODM_WT.MM.Display.Lcd, 2018/08/09, LCD voltage control */
/* #endif */
/* #ifdef ODM_WT_EDIT */
/* Jinfan.Hu@ODM_WT.BSP.Kernel.Boot, 2018/12/7, Add for serial mode change */
&uart0{
	pinctrl-names = "serial_urxd0","serial_gpio_rx","serial_utxd0","serial_gpio_tx";
	pinctrl-0 = <&serial_urxd0>;
	pinctrl-1 = <&serial_gpio_rx>;
	pinctrl-2 = <&serial_utxd0>;
	pinctrl-3 = <&serial_gpio_tx>;
	status = "okay";
};

&pio {
	serial_urxd0: serial_urxd0 {
                pins_cmd_dat {
                        pinmux = <PINMUX_GPIO95__FUNC_URXD0>;
                        slew-rate = <1>;
                };
        };
	serial_gpio_rx: serial_gpio_rx {
		pins_cmd_dat {
                        pinmux = <PINMUX_GPIO95__FUNC_GPIO95>;
                        slew-rate = <1>;
                        input-low;
                };
        };
	serial_utxd0: serial_utxd0 {
                pins_cmd_dat {
                        pinmux = <PINMUX_GPIO96__FUNC_UTXD0>;
                        slew-rate = <1>;
                };
        };
	serial_gpio_tx: serial_gpio_tx {
		pins_cmd_dat {
                        pinmux = <PINMUX_GPIO96__FUNC_GPIO96>;
                        slew-rate = <1>;
                        input-low;
                };
        };
};
/* #endif */
#include <oppo6765_18510/cust.dtsi>
/*End of this file, DO NOT ADD ANYTHING HERE*/
